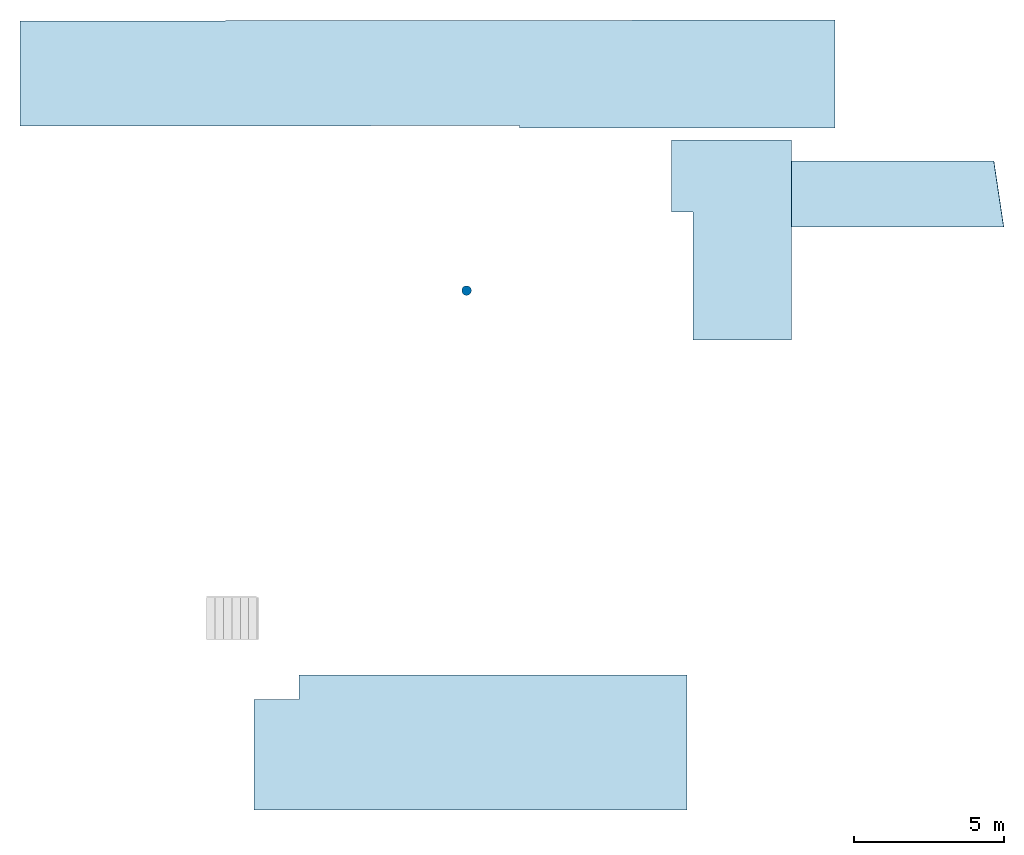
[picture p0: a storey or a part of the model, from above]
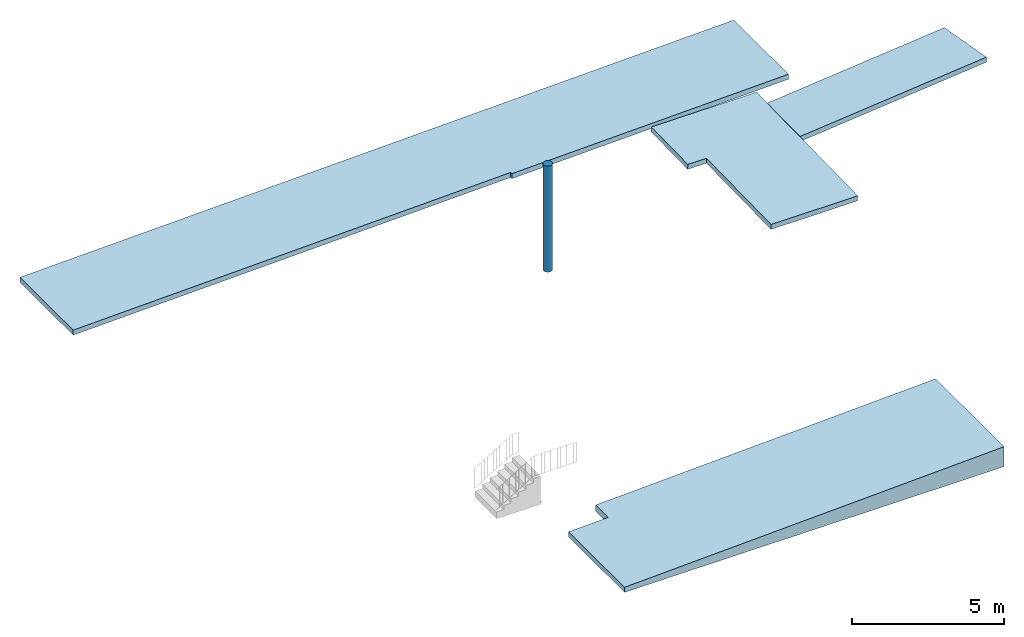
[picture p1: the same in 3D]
Properties of the parts of a building model (IFC2X3), part 1 of 3

# File
Description: ViewDefinition [CoordinationView_V2.0], RevitIdentifiers [VersionGUID: 12e980eb-f1c6-4dce-955d-64f03844660f, NumberOfSaves: 0], CoordinateReference [CoordinateBase: Coordonnées partagées]
File name: 0001
Time: 2023-09-28T10:16:39+01:00
Written by: ODA SDAI 22.12
Made in: 23.1.10.4 - Exporter 23.2.2.0 - Interface utilisateur alternative 23.2.2.0

# IfcProject, 0001
LongName: Nom du projet; Phase: Etat du projet

# IfcSite, Default
RefLatitude: 46, 9, 59, 999999; RefLongitude: 6, 8, 59, 999999; RefElevation: 0 m

# IfcSite: Site:Site, Site:Site:162049
Material: Peinture - Beige sable

# IfcBuilding
Pset_BuildingCommon - NumberOfStoreys: 6

# IfcBuildingStorey: Niveau:Pointe 8 mm (11)
Name | LongName | Elevation (m)
bloc-sanitaire | bloc-sanitaire | -7
GÉOMÈTRE estibal | GÉOMÈTRE estibal | -6
GÉOMÈTRE topo | GÉOMÈTRE topo | -5
GÉOMÈTRE avant bibliobus | GÉOMÈTRE avant bibliobus | -4
EDL RDC | EDL RDC | -3
EDL R+1 | EDL R+1 | -2
VS | VS | -1
REZ-DE-CHAUSSÉE | REZ-DE-CHAUSSÉE | 0
ÉTAGE | ÉTAGE | 3.06
TOITURE | TOITURE | 6.06
PLAN DE MASSE | PLAN DE MASSE | 9.06

# IfcBeam: Poutre-002 805777:Poutre-002 805777, Poutre-002
In: ÉTAGE
Type - Pset_BeamCommon - LoadBearing: yes; IsExternal: no
Material: Enduit - Beige nature
Pset_BeamCommon - Reference: BE béton 620 x 540
Pset_QuantityTakeOff - Reference: BE béton 620 x 540; sets with these values: 2

# IfcBeam: Poutre-002 805953:Poutre-002 805953, Poutre-002
In: ÉTAGE
Type - Pset_BeamCommon - LoadBearing: yes; IsExternal: no
Material: Peinture - Jade pâle
Pset_BeamCommon - Reference: BE acier 550 x 3000
Pset_QuantityTakeOff - Reference: BE acier 550 x 3000; sets with these values: 2

# IfcBeam: Poutre-004 250637:Poutre-004 250637 (5)
Type - Pset_BeamCommon - LoadBearing: yes; IsExternal: no
Material: Enduit - Beige nature
Pset_BeamCommon - Reference: BE béton 620 x 540
Pset_QuantityTakeOff - Reference: BE béton 620 x 540; sets with these values: 2
Name | In
Poutre-002 | TOITURE
Poutre-011 | ÉTAGE
Poutre-009 | ÉTAGE
Poutre-007 | ÉTAGE
Poutre-004 | ÉTAGE

# IfcBeam: Poutre-005 250586:Poutre-005 250586, Poutre-005
In: REZ-DE-CHAUSSÉE
Type - Pset_BeamCommon - LoadBearing: yes; IsExternal: no
Material: Enduit - Beige nature
Pset_BeamCommon - Reference: BE béton 620 x 540
Pset_QuantityTakeOff - Reference: BE béton 620 x 540; sets with these values: 2

# IfcBeam: Poutre-010 250417:Poutre-010 250417 (6)
Type - Pset_BeamCommon - LoadBearing: yes; IsExternal: no
Material: Peinture - Jade pâle
Pset_BeamCommon - Reference: BE acier 550 x 3000
Pset_QuantityTakeOff - Reference: BE acier 550 x 3000; sets with these values: 2
Name | In
Poutre-002 | TOITURE
Poutre-004 | ÉTAGE
Poutre-012 | ÉTAGE
Poutre-006 | ÉTAGE
Poutre-008 | ÉTAGE
Poutre-010 | ÉTAGE

# IfcBeam: Poutre-011 251190:Poutre-011 251190, Poutre-011
In: REZ-DE-CHAUSSÉE
Type - Pset_BeamCommon - LoadBearing: yes; IsExternal: no
Material: Enduit - Beige nature
Pset_BeamCommon - Reference: BE béton 620 x 540
Pset_QuantityTakeOff - Reference: BE béton 620 x 540; sets with these values: 2

# IfcBeam: Poutre-013 804316:Poutre-013 804316, Poutre-013
In: TOITURE
Type - Pset_BeamCommon - LoadBearing: yes; IsExternal: no
Material: Bois - Pin granuleux horizontal
Pset_BeamCommon - Reference: Bois - Massif 01 150 x 400
Pset_QuantityTakeOff - Reference: Bois - Massif 01 150 x 400; sets with these values: 2

# IfcBeam: Poutre-013 825176:Poutre-013 825176, Poutre-013
In: TOITURE
Type - Pset_BeamCommon - LoadBearing: yes; IsExternal: no
Material: Bois - Pin granuleux horizontal
Pset_BeamCommon - Reference: Bois - Massif 01 150 x 400
Pset_QuantityTakeOff - Reference: Bois - Massif 01 150 x 400; sets with these values: 2

# IfcBeam: Poutre-015 274921:Poutre-015 274921, Poutre-015
In: REZ-DE-CHAUSSÉE
Type - Pset_BeamCommon - LoadBearing: yes; IsExternal: no
Material: Bois - Pin granuleux horizontal
Pset_BeamCommon - Reference: Bois - Massif 01 200 x 150
Pset_QuantityTakeOff - Reference: Bois - Massif 01 200 x 150; sets with these values: 2

# IfcBeam: Poutre-017 441781:Poutre-017 441781, Poutre-017
In: ÉTAGE
Type - Pset_BeamCommon - LoadBearing: yes; IsExternal: no
Material: Peinture - Gris foncé
Pset_BeamCommon - Reference: grille 110x120 1100 x 1200
Pset_QuantityTakeOff - Reference: grille 110x120 1100 x 1200; sets with these values: 2

# IfcBeam: Poutre-017 448176:Poutre-017 448176 (5)
In: ÉTAGE
Type - Pset_BeamCommon - LoadBearing: yes; IsExternal: no
Material: Peinture - Gris foncé
Pset_BeamCommon - Reference: grille 110x170 1100 x 1700
Pset_QuantityTakeOff - Reference: grille 110x170 1100 x 1700; sets with these values: 2

# IfcBeam: Poutre-017 457192:Poutre-017 457192 (2)
In: ÉTAGE
Type - Pset_BeamCommon - LoadBearing: yes; IsExternal: no
Material: Peinture - Gris foncé
Pset_BeamCommon - Reference: grille 100x250 1000 x 2500
Pset_QuantityTakeOff - Reference: grille 100x250 1000 x 2500; sets with these values: 2

# IfcBeam: Poutre-017 458672:Poutre-017 458672 (4)
In: ÉTAGE
Type - Pset_BeamCommon - LoadBearing: yes; IsExternal: no
Material: Peinture - Gris foncé
Pset_BeamCommon - Reference: grille 50x245_1 510 x 2460
Pset_QuantityTakeOff - Reference: grille 50x245_1 510 x 2460; sets with these values: 2

# IfcBeam: Poutre-017 458855:Poutre-017 458855 (4)
In: ÉTAGE
Type - Pset_BeamCommon - LoadBearing: yes; IsExternal: no
Material: Peinture - Gris foncé
Pset_BeamCommon - Reference: grille 50x245_2 510 x 2460
Pset_QuantityTakeOff - Reference: grille 50x245_2 510 x 2460; sets with these values: 2

# IfcBeam: Poutre-017 459038:Poutre-017 459038 (4)
In: ÉTAGE
Type - Pset_BeamCommon - LoadBearing: yes; IsExternal: no
Material: Peinture - Gris foncé
Pset_BeamCommon - Reference: grille 50x245_3 510 x 2460
Pset_QuantityTakeOff - Reference: grille 50x245_3 510 x 2460; sets with these values: 2

# IfcBeam: Poutre-017 459230:Poutre-017 459230 (6)
In: ÉTAGE
Type - Pset_BeamCommon - LoadBearing: yes; IsExternal: no
Material: Peinture - Gris foncé
Pset_BeamCommon - Reference: grille 50x245_3 510 x 2460
Pset_QuantityTakeOff - Reference: grille 50x245_3 510 x 2460; sets with these values: 2

# IfcBeam: Poutre-017 459277:Poutre-017 459277 (6)
In: ÉTAGE
Type - Pset_BeamCommon - LoadBearing: yes; IsExternal: no
Material: Peinture - Gris foncé
Pset_BeamCommon - Reference: grille 50x245_2 510 x 2460
Pset_QuantityTakeOff - Reference: grille 50x245_2 510 x 2460; sets with these values: 2

# IfcBeam: Poutre-017 459324:Poutre-017 459324 (6)
In: ÉTAGE
Type - Pset_BeamCommon - LoadBearing: yes; IsExternal: no
Material: Peinture - Gris foncé
Pset_BeamCommon - Reference: grille 50x245_1 510 x 2460
Pset_QuantityTakeOff - Reference: grille 50x245_1 510 x 2460; sets with these values: 2

# IfcBeam: Poutre-018 48198:Poutre-018 48198 (2)
In: REZ-DE-CHAUSSÉE
Type - Pset_BeamCommon - LoadBearing: yes; IsExternal: no
Material: Peinture - Gris foncé
Pset_BeamCommon - Reference: grille 105x150 1050 x 1500
Pset_QuantityTakeOff - Reference: grille 105x150 1050 x 1500; sets with these values: 2

# IfcBeam: Poutre-019 150027:Poutre-019 150027, Poutre-019
In: ÉTAGE
Type - Pset_BeamCommon - LoadBearing: yes; IsExternal: no
Material: Peinture - Gris foncé
Pset_BeamCommon - Reference: Tube: C - simple 60 x 160
Pset_QuantityTakeOff - Reference: Tube: C - simple 60 x 160; sets with these values: 2

# IfcBeam: Poutre-019 150105:Poutre-019 150105 (2)
In: REZ-DE-CHAUSSÉE
Type - Pset_BeamCommon - LoadBearing: yes; IsExternal: no
Material: Peinture - Gris foncé
Pset_BeamCommon - Reference: IPN 200 70 x 140
Pset_QuantityTakeOff - Reference: IPN 200 70 x 140; sets with these values: 2

# IfcBeam: Poutre-019 150203:Poutre-019 150203 (5)
In: REZ-DE-CHAUSSÉE
Type - Pset_BeamCommon - LoadBearing: yes; IsExternal: no
Material: Peinture - Gris foncé
Pset_BeamCommon - Reference: IPN 200 70 x 140
Pset_QuantityTakeOff - Reference: IPN 200 70 x 140; sets with these values: 2

# IfcBeam: Poutre-019 150363:Poutre-019 150363, Poutre-019
In: ÉTAGE
Type - Pset_BeamCommon - LoadBearing: yes; IsExternal: no
Material: Peinture - Gris foncé
Pset_BeamCommon - Reference: Tube: C - simple 60 x 140
Pset_QuantityTakeOff - Reference: Tube: C - simple 60 x 140; sets with these values: 2

# IfcBeam: Poutre-019 150414:Poutre-019 150414, Poutre-019
In: ÉTAGE
Type - Pset_BeamCommon - LoadBearing: yes; IsExternal: no
Material: Peinture - Gris foncé
Pset_BeamCommon - Reference: Tube: C - simple 60 x 140
Pset_QuantityTakeOff - Reference: Tube: C - simple 60 x 140; sets with these values: 2

# IfcBeam: Poutre-019 150508:Poutre-019 150508, Poutre-019
In: ÉTAGE
Type - Pset_BeamCommon - LoadBearing: yes; IsExternal: no
Material: Métal - Acier
Pset_BeamCommon - Reference: IPN 200 50 x 100
Pset_QuantityTakeOff - Reference: IPN 200 50 x 100; sets with these values: 2

# IfcBeam: Poutre-019 150673:Poutre-019 150673, Poutre-019
In: ÉTAGE
Type - Pset_BeamCommon - LoadBearing: yes; IsExternal: no
Material: Métal - Acier
Pset_BeamCommon - Reference: IPN 200 50 x 100
Pset_QuantityTakeOff - Reference: IPN 200 50 x 100; sets with these values: 2

# IfcBeam: Poutre-019 150740:Poutre-019 150740, Poutre-019
In: ÉTAGE
Type - Pset_BeamCommon - LoadBearing: yes; IsExternal: no
Material: Métal - Acier
Pset_BeamCommon - Reference: IPN 200 50 x 100
Pset_QuantityTakeOff - Reference: IPN 200 50 x 100; sets with these values: 2

# IfcBeam: Poutre-019 150807:Poutre-019 150807, Poutre-019
In: ÉTAGE
Type - Pset_BeamCommon - LoadBearing: yes; IsExternal: no
Material: Métal - Acier
Pset_BeamCommon - Reference: IPN 200 50 x 100
Pset_QuantityTakeOff - Reference: IPN 200 50 x 100; sets with these values: 2

# IfcBeam: Poutre-019 150874:Poutre-019 150874, Poutre-019
In: ÉTAGE
Type - Pset_BeamCommon - LoadBearing: yes; IsExternal: no
Material: Métal - Acier
Pset_BeamCommon - Reference: IPN 200 50 x 100
Pset_QuantityTakeOff - Reference: IPN 200 50 x 100; sets with these values: 2

# IfcBeam: Poutre-019 19330:Poutre-019 19330, Poutre-019
In: ÉTAGE
Type - Pset_BeamCommon - LoadBearing: yes; IsExternal: no
Material: Peinture - Gris foncé
Pset_BeamCommon - Reference: Tube: C - simple 70 x 180
Pset_QuantityTakeOff - Reference: Tube: C - simple 70 x 180; sets with these values: 2

# IfcBeam: Poutre-019 56232:Poutre-019 56232, Poutre-019
In: ÉTAGE
Type - Pset_BeamCommon - LoadBearing: yes; IsExternal: no
Material: Peinture - Gris foncé
Pset_BeamCommon - Reference: Tube: C - simple 70 x 100
Pset_QuantityTakeOff - Reference: Tube: C - simple 70 x 100; sets with these values: 2

# IfcBuildingElementProxy: Poutre-001 244787:Poutre-001 244787, Poutre-001 244787:Poutre-001 244787:151923
In: ÉTAGE
Type - Material: Bois - Chêne clair
Pset_BuildingElementProxyCommon - Reference: Poutre-001 244787; sets with these values: 2

# IfcBuildingElementProxy: Poutre-001 248392:Poutre-001 248392, Poutre-001 248392:Poutre-001 248392:151969
In: ÉTAGE
Type - Material: Bois - Chêne clair
Pset_BuildingElementProxyCommon - Reference: Poutre-001 248392; sets with these values: 2

# IfcBuildingElementProxy: Poutre-001:Poutre-001, Poutre-001:Poutre-001:147980
In: REZ-DE-CHAUSSÉE
Type - Material: Bois - Chêne clair
Pset_BuildingElementProxyCommon - Reference: Poutre-001; sets with these values: 2

# IfcBuildingElementProxy: Poutre-016 844062:Poutre-016 844062, Poutre-016 844062:Poutre-016 844062:161965
In: REZ-DE-CHAUSSÉE
Type - Material: Peinture - Gris foncé
Pset_BuildingElementProxyCommon - Reference: Poutre-016 844062; sets with these values: 2
Pset_ProvisionForVoid - Width: 0.06 m; Height: 0.04 m; Depth: 0.04 m

# IfcBuildingElementProxy: Poutre-016:Poutre-016, Poutre-016:Poutre-016:161553
In: TOITURE
Type - Material: Peinture - Gris foncé
Pset_BuildingElementProxyCommon - Reference: Poutre-016; sets with these values: 2

# IfcBuildingElementProxy: Symb-0001 (6)
Type - Material: Déco - Céramique / Porcelaine
Pset_BuildingElementProxyCommon - sets with these values: 2
Name | In | Reference
Symb-0001:Symb-0001:148294 | REZ-DE-CHAUSSÉE | Symb-0001
Symb-0001 105909:Symb-0001 105909:150008 | REZ-DE-CHAUSSÉE | Symb-0001 105909
Symb-0001 265598:Symb-0001 265598:152434 | ÉTAGE | Symb-0001 265598
Symb-0001 267370:Symb-0001 267370:152441 | ÉTAGE | Symb-0001 267370
Symb-0001 271945:Symb-0001 271945:152448 | ÉTAGE | Symb-0001 271945
Symb-0001 801620:Symb-0001 801620:161433 | ÉTAGE | Symb-0001 801620

# IfcBuildingElementProxy: Symb-0001, Symb-0001 47900:Symb-0001 47900:148666
In: REZ-DE-CHAUSSÉE
Type - Material: Marbre - Blanc beige
Pset_BuildingElementProxyCommon - Reference: Symb-0001 47900; sets with these values: 2

# IfcBuildingElementProxy: Symb-0001, Symb-0001 249329:Symb-0001 249329:152008
In: ÉTAGE
Type - Material: Peinture - Gris foncé
Pset_BuildingElementProxyCommon - Reference: Symb-0001 249329; sets with these values: 2

# IfcBuildingElementProxy: Symb-0002 (2)
In: ÉTAGE
Type - Material: Métal - Chrome, Métal - Zinc, Peinture - Blanc titanium, Peinture - Noir, Transp. - Verre bleuté, Métal - Fer 16274
Pset_BuildingElementProxyCommon - sets with these values: 2
Name | Reference
Symb-0002 440074:Symb-0002 440074:156005 | Symb-0002 440074
Symb-0002 453781:Symb-0002 453781:158489 | Symb-0002 453781

# IfcBuildingElementProxy: Symb-0002 (3)
In: TOITURE
Type - Material: Métal - Zinc
Pset_BuildingElementProxyCommon - sets with these values: 2
Pset_ProvisionForVoid - Width: 0.3 m; Height: 0.3 m; Depth: 0.3 m
Name | Reference
Symb-0002 824208:Symb-0002 824208:161709 | Symb-0002 824208
Symb-0002 842974:Symb-0002 842974:161895 | Symb-0002 842974
Symb-0002 843032:Symb-0002 843032:161916 | Symb-0002 843032

# IfcBuildingElementProxy: Symb-0002, Symb-0002:Symb-0002:151962
In: ÉTAGE
Type - Material: Peinture - Anthracite
Pset_BuildingElementProxyCommon - Reference: Symb-0002; sets with these values: 2

# IfcBuildingElementProxy: Symb-0003 (17)
Type - Material: Bois - Chêne clair
Pset_BuildingElementProxyCommon - sets with these values: 2
Name | In | Reference | Width (m) | Height (m) = Depth (m)
Symb-0003:Symb-0003:148089 | REZ-DE-CHAUSSÉE | Symb-0003 | 0.1 | 0.02
Symb-0003 60907:Symb-0003 60907:148702 | REZ-DE-CHAUSSÉE | Symb-0003 60907 | 0.1 | 0.02
Symb-0003 60936:Symb-0003 60936:148765 | REZ-DE-CHAUSSÉE | Symb-0003 60936 | 0.1 | 0.02
Symb-0003 60965:Symb-0003 60965:148828 | REZ-DE-CHAUSSÉE | Symb-0003 60965 | 0.1 | 0.02
Symb-0003 60994:Symb-0003 60994:148891 | REZ-DE-CHAUSSÉE | Symb-0003 60994 | 0.1 | 0.02
Symb-0003 61023:Symb-0003 61023:148954 | REZ-DE-CHAUSSÉE | Symb-0003 61023 | 0.1 | 0.02
Symb-0003 62364:Symb-0003 62364:149017 | REZ-DE-CHAUSSÉE | Symb-0003 62364 | 0.102 | 0.02
Symb-0003 62445:Symb-0003 62445:149199 | REZ-DE-CHAUSSÉE | Symb-0003 62445 | 0.102 | 0.02
Symb-0003 63828:Symb-0003 63828:149381 | REZ-DE-CHAUSSÉE | Symb-0003 63828 | 0.102 | 0.02
Symb-0003 65325:Symb-0003 65325:149563 | REZ-DE-CHAUSSÉE | Symb-0003 65325 | 0.1 | 0.02
Symb-0003 104089:Symb-0003 104089:149819 | REZ-DE-CHAUSSÉE | Symb-0003 104089 | 0.1 | 0.02
Symb-0003 133649:Symb-0003 133649:150591 | REZ-DE-CHAUSSÉE | Symb-0003 133649 | 0.1 | 0.02
Symb-0003 134108:Symb-0003 134108:150661 | REZ-DE-CHAUSSÉE | Symb-0003 134108 | 0.1 | 0.02
Symb-0003 134189:Symb-0003 134189:150724 | REZ-DE-CHAUSSÉE | Symb-0003 134189 | 0.1 | 0.02
Symb-0003 134270:Symb-0003 134270:150787 | REZ-DE-CHAUSSÉE | Symb-0003 134270 | 0.1 | 0.02
Symb-0003 134351:Symb-0003 134351:150850 | REZ-DE-CHAUSSÉE | Symb-0003 134351 | 0.1 | 0.02
Symb-0003 290547:Symb-0003 290547:155177 | ÉTAGE | Symb-0003 290547 | 3.44 | 0.05

# IfcBuildingElementProxy: Symb-0003 (3)
In: ÉTAGE
Type - Material: Métal - Zinc
Pset_BuildingElementProxyCommon - sets with these values: 2
Name | Reference
Symb-0003 824296:Symb-0003 824296:161723 | Symb-0003 824296
Symb-0003 842945:Symb-0003 842945:161888 | Symb-0003 842945
Symb-0003 843003:Symb-0003 843003:161909 | Symb-0003 843003

# IfcBuildingElementProxy: Symb-0003 (11)
Type - Material: Peinture - Anthracite
Pset_BuildingElementProxyCommon - sets with these values: 2
Name | In | Reference | Width (m) | Height (m) = Depth (m)
Symb-0003 46987:Symb-0003 46987:148501 | REZ-DE-CHAUSSÉE | Symb-0003 46987 | 2.2 | 3.3
Symb-0003 254697:Symb-0003 254697:152288 | ÉTAGE | Symb-0003 254697 | 2.48 | 3.4
Symb-0003 274880:Symb-0003 274880:152455 | ÉTAGE | Symb-0003 274880
Symb-0003 282040:Symb-0003 282040:152468 | ÉTAGE | Symb-0003 282040 | 2.76 | 3.3
Symb-0003 285634:Symb-0003 285634:153152 | ÉTAGE | Symb-0003 285634 | 2.15 | 3
Symb-0003 297244:Symb-0003 297244:155510 | ÉTAGE | Symb-0003 297244 | 0.04 | 0.01
Symb-0003 299875:Symb-0003 299875:155608 | ÉTAGE | Symb-0003 299875 | 5.25 | 0.04
Symb-0003 463800:Symb-0003 463800:158503 | REZ-DE-CHAUSSÉE | Symb-0003 463800
Symb-0003 467921:Symb-0003 467921:160031 | ÉTAGE | Symb-0003 467921 | 3.4 | 0.04
Symb-0003 470760:Symb-0003 470760:160276 | ÉTAGE | Symb-0003 470760 | 5.55 | 0.04
Symb-0003 472838:Symb-0003 472838:160661 | ÉTAGE | Symb-0003 472838 | 2.48 | 3.3

# IfcBuildingElementProxy: Symb-0003 (18)
In: ÉTAGE
Type - Material: Peinture - Gris foncé
Pset_BuildingElementProxyCommon - sets with these values: 2
Pset_ProvisionForVoid - Width: 0.04 m; Height: 0.04 m; Depth: 0.04 m
Name | Reference
Symb-0003 283937:Symb-0003 283937:152675 | Symb-0003 283937
Symb-0003 284028:Symb-0003 284028:152905 | Symb-0003 284028
Symb-0003 285663:Symb-0003 285663:153317 | Symb-0003 285663
Symb-0003 285692:Symb-0003 285692:153547 | Symb-0003 285692
Symb-0003 285721:Symb-0003 285721:153777 | Symb-0003 285721
Symb-0003 287706:Symb-0003 287706:154230 | Symb-0003 287706
Symb-0003 288161:Symb-0003 288161:154474 | Symb-0003 288161
Symb-0003 288190:Symb-0003 288190:154704 | Symb-0003 288190
Symb-0003 288219:Symb-0003 288219:154934 | Symb-0003 288219
Symb-0003 464579:Symb-0003 464579:158979 | Symb-0003 464579
Symb-0003 464608:Symb-0003 464608:159079 | Symb-0003 464608
Symb-0003 464637:Symb-0003 464637:159179 | Symb-0003 464637
Symb-0003 464666:Symb-0003 464666:159279 | Symb-0003 464666
Symb-0003 464695:Symb-0003 464695:159379 | Symb-0003 464695
Symb-0003 464724:Symb-0003 464724:159479 | Symb-0003 464724
Symb-0003 464753:Symb-0003 464753:159579 | Symb-0003 464753
Symb-0003 464782:Symb-0003 464782:159679 | Symb-0003 464782
Symb-0003 464811:Symb-0003 464811:159779 | Symb-0003 464811

# IfcBuildingElementProxy: Symb-0004 (10)
In: REZ-DE-CHAUSSÉE
Type - Material: Air - Vide d'air
Pset_BuildingElementProxyCommon - sets with these values: 2
Name | Reference
Symb-0004:Symb-0004:148694 | Symb-0004
Symb-0004 86494:Symb-0004 86494:149763 | Symb-0004 86494
Symb-0004 87821:Symb-0004 87821:149770 | Symb-0004 87821
Symb-0004 89785:Symb-0004 89785:149777 | Symb-0004 89785
Symb-0004 92138:Symb-0004 92138:149784 | Symb-0004 92138
Symb-0004 93556:Symb-0004 93556:149791 | Symb-0004 93556
Symb-0004 96958:Symb-0004 96958:149798 | Symb-0004 96958
Symb-0004 100234:Symb-0004 100234:149805 | Symb-0004 100234
Symb-0004 103848:Symb-0004 103848:149812 | Symb-0004 103848
Symb-0004 129922:Symb-0004 129922:150575 | Symb-0004 129922

# IfcBuildingElementProxy: Symb-0004, Symb-0004 124967:Symb-0004 124967:150022
In: VS
Type - Material: Peinture - Gris clair
Pset_BuildingElementProxyCommon - Reference: Symb-0004 124967; sets with these values: 2

# IfcBuildingElementProxy: Symb-0004 (2)
In: ÉTAGE
Type - Material: Peinture - Gris foncé
Pset_BuildingElementProxyCommon - sets with these values: 2
Pset_ProvisionForVoid - Width: 0.02 m; Height: 0.04 m; Depth: 0.04 m
Name | Reference
Symb-0004 286920:Symb-0004 286920:154123 | Symb-0004 286920
Symb-0004 466004:Symb-0004 466004:159879 | Symb-0004 466004

# IfcColumn: Pot-001 17298:Pot-001 17298, Pot-001
In: EDL R+1
Type - PredefinedType: COLUMN; Material: <Unnamed>, Surface-Blanc
Type - Pset_ColumnCommon - LoadBearing: yes; IsExternal: no
Material: Surface-Blanc
Pset_ColumnCommon - Reference: Struct. - Pierre D320
Pset_QuantityTakeOff - Reference: Struct. - Pierre D320; sets with these values: 2

# IfcColumn: Pot-001 17357:Pot-001 17357 (6)
In: REZ-DE-CHAUSSÉE
Type - PredefinedType: COLUMN; Material: Surface-Blanc
Type - Pset_ColumnCommon - LoadBearing: yes; IsExternal: no
Pset_ColumnCommon - Reference: Struct. - Pierre D340
Pset_QuantityTakeOff - Reference: Struct. - Pierre D340; sets with these values: 2
Name
2 x Pot-003
2 x Pot-002
2 x Pot-001

# IfcColumn: Pot-003 25818:Pot-003 25818 (2)
In: REZ-DE-CHAUSSÉE
Type - PredefinedType: COLUMN; Material: Enduit - Beige nature
Type - Pset_ColumnCommon - LoadBearing: yes; IsExternal: no
Pset_ColumnCommon - Reference: Struct. - Pierre 260 x 260
Pset_QuantityTakeOff - Reference: Struct. - Pierre 260 x 260; sets with these values: 2
Name
Pot-004
Pot-003

# IfcColumn: Pot-005 285852:Pot-005 285852, Pot-005 285852:Pot-005 285852:154036
In: ÉTAGE
Type - PredefinedType: COLUMN; Material: Peinture - Gris foncé
Type - Pset_ColumnCommon - IsExternal: no
Pset_ColumnCommon - Reference: Pot-005 285852
Pset_QuantityTakeOff - Reference: Pot-005 285852; sets with these values: 2

# IfcColumn: Pot-005 285958:Pot-005 285958, Pot-005 285958:Pot-005 285958:154065
In: ÉTAGE
Type - PredefinedType: COLUMN; Material: Peinture - Gris foncé
Type - Pset_ColumnCommon - IsExternal: no
Pset_ColumnCommon - Reference: Pot-005 285958
Pset_QuantityTakeOff - Reference: Pot-005 285958; sets with these values: 2

# IfcColumn: Pot-005 286064:Pot-005 286064, Pot-005 286064:Pot-005 286064:154094
In: ÉTAGE
Type - PredefinedType: COLUMN; Material: Peinture - Gris foncé
Type - Pset_ColumnCommon - IsExternal: no
Pset_ColumnCommon - Reference: Pot-005 286064
Pset_QuantityTakeOff - Reference: Pot-005 286064; sets with these values: 2

# IfcColumn: Pot-005 441838:Pot-005 441838 (65)
In: ÉTAGE
Type - PredefinedType: COLUMN; Material: Peinture - Gris foncé
Type - Pset_ColumnCommon - LoadBearing: yes; IsExternal: no
Pset_ColumnCommon - Reference: Métal - Fer 6 x 30
Pset_QuantityTakeOff - Reference: Métal - Fer 6 x 30; sets with these values: 2

# IfcColumn: Pot-005 447493:Pot-005 447493 (32)
In: ÉTAGE
Type - PredefinedType: COLUMN; Material: Peinture - Gris foncé
Type - Pset_ColumnCommon - LoadBearing: yes; IsExternal: no
Pset_ColumnCommon - Reference: Métal - Fer 30 x 6
Pset_QuantityTakeOff - Reference: Métal - Fer 30 x 6; sets with these values: 2

# IfcColumn: Pot-005 459659:Pot-005 459659, Pot-005
In: ÉTAGE
Type - PredefinedType: COLUMN; Material: <Unnamed>, Peinture - Gris foncé
Type - Pset_ColumnCommon - LoadBearing: yes; IsExternal: no
Material: Peinture - Gris foncé
Pset_ColumnCommon - Reference: Métal - Fer 80 x 140
Pset_QuantityTakeOff - Reference: Métal - Fer 80 x 140; sets with these values: 2

# IfcColumn: Pot-005:Pot-005, Pot-005:Pot-005:154007
In: ÉTAGE
Type - PredefinedType: COLUMN; Material: Peinture - Gris foncé
Type - Pset_ColumnCommon - IsExternal: no
Pset_ColumnCommon - Reference: Pot-005
Pset_QuantityTakeOff - Reference: Pot-005; sets with these values: 2

# IfcColumn: Pot-006 103892:Pot-006 103892 (24)
In: REZ-DE-CHAUSSÉE
Type - PredefinedType: COLUMN; Material: Peinture - Gris foncé
Type - Pset_ColumnCommon - LoadBearing: yes; IsExternal: no
Pset_ColumnCommon - Reference: Métal - Fer 100 x 50
Pset_QuantityTakeOff - Reference: Métal - Fer 100 x 50; sets with these values: 2
Name
20 x Pot-007
4 x Pot-006

# IfcColumn: Pot-006 134395:Pot-006 134395, Pot-006
In: VS
Type - PredefinedType: COLUMN; Material: <Unnamed>, Peinture - Gris foncé
Type - Pset_ColumnCommon - LoadBearing: yes; IsExternal: no
Material: Peinture - Gris foncé
Pset_ColumnCommon - Reference: Métal - Fer 10 x 100
Pset_QuantityTakeOff - Reference: Métal - Fer 10 x 100; sets with these values: 2

# IfcColumn: Pot-006 56846:Pot-006 56846 (23)
In: REZ-DE-CHAUSSÉE
Type - PredefinedType: COLUMN; Material: Peinture - Gris foncé
Type - Pset_ColumnCommon - LoadBearing: yes; IsExternal: no
Pset_ColumnCommon - Reference: Métal - Fer 50 x 100
Pset_QuantityTakeOff - Reference: Métal - Fer 50 x 100; sets with these values: 2

# IfcColumn: Pot-008 40407:Pot-008 40407 (4)
In: REZ-DE-CHAUSSÉE
Type - PredefinedType: COLUMN; Material: Bois - Chêne clair
Type - Pset_ColumnCommon - LoadBearing: yes; IsExternal: no
Pset_ColumnCommon - Reference: Bois - Massif 01 70 x 140
Pset_QuantityTakeOff - Reference: Bois - Massif 01 70 x 140; sets with these values: 2
Name
Pot-007
3 x Pot-008

# IfcColumn: Pot-010 24125:Pot-010 24125, Pot-010
In: REZ-DE-CHAUSSÉE
Type - PredefinedType: COLUMN; Material: <Unnamed>, Bois - Chêne clair
Type - Pset_ColumnCommon - LoadBearing: yes; IsExternal: no
Material: Bois - Chêne clair
Pset_ColumnCommon - Reference: Bois - Massif 01 60 x 140
Pset_QuantityTakeOff - Reference: Bois - Massif 01 60 x 140; sets with these values: 2

# IfcColumn: Pot-011 135416:Pot-011 135416 (3)
In: REZ-DE-CHAUSSÉE
Type - PredefinedType: COLUMN; Material: Béton - Lissé
Type - Pset_ColumnCommon - LoadBearing: yes; IsExternal: no
Pset_ColumnCommon - Reference: Struct. - Béton 100 x 100
Pset_QuantityTakeOff - Reference: Struct. - Béton 100 x 100; sets with these values: 2

# IfcColumn: Pot-011 135587:Pot-011 135587, Pot-011
In: VS
Type - PredefinedType: COLUMN; Material: <Unnamed>, Béton - Lissé
Type - Pset_ColumnCommon - LoadBearing: yes; IsExternal: no
Material: Béton - Lissé
Pset_ColumnCommon - Reference: Struct. - Béton 100 x 100
Pset_QuantityTakeOff - Reference: Struct. - Béton 100 x 100; sets with these values: 2

# IfcColumn: Pot-012 448235:Pot-012 448235 (2)
In: ÉTAGE
Type - PredefinedType: COLUMN; Material: Peinture - Gris foncé
Type - Pset_ColumnCommon - LoadBearing: yes; IsExternal: no
Pset_ColumnCommon - Reference: Bois - Massif 01 240 x 120
Pset_QuantityTakeOff - Reference: Bois - Massif 01 240 x 120; sets with these values: 2

# IfcDiscreteAccessory: Symb-0003 (17)
In: REZ-DE-CHAUSSÉE
Type - Material: Bois - Chêne clair
Name | Reference
Symb-0003 449563:Symb-0003 449563:156160 | Symb-0003 449563
Symb-0003 449597:Symb-0003 449597:156297 | Symb-0003 449597
Symb-0003 449627:Symb-0003 449627:156434 | Symb-0003 449627
Symb-0003 449657:Symb-0003 449657:156571 | Symb-0003 449657
Symb-0003 449687:Symb-0003 449687:156708 | Symb-0003 449687
Symb-0003 450779:Symb-0003 450779:156845 | Symb-0003 450779
Symb-0003 451881:Symb-0003 451881:156982 | Symb-0003 451881
Symb-0003 451911:Symb-0003 451911:157119 | Symb-0003 451911
Symb-0003 451941:Symb-0003 451941:157256 | Symb-0003 451941
Symb-0003 453043:Symb-0003 453043:157393 | Symb-0003 453043
Symb-0003 453073:Symb-0003 453073:157530 | Symb-0003 453073
Symb-0003 453103:Symb-0003 453103:157667 | Symb-0003 453103
Symb-0003 453133:Symb-0003 453133:157804 | Symb-0003 453133
Symb-0003 453163:Symb-0003 453163:157941 | Symb-0003 453163
Symb-0003 453193:Symb-0003 453193:158078 | Symb-0003 453193
Symb-0003 453223:Symb-0003 453223:158215 | Symb-0003 453223
Symb-0003 453253:Symb-0003 453253:158352 | Symb-0003 453253

# IfcDiscreteAccessory: Symb-0004, Symb-0004 240046:Symb-0004 240046:151657
In: ÉTAGE
Type - Material: Peinture - Blanc titanium
Pset_QuantityTakeOff - Reference: Symb-0004 240046

# IfcDiscreteAccessory: Symb-0005, Symb-0005:Symb-0005:151706
In: REZ-DE-CHAUSSÉE
Type - Material: Peinture - Blanc titanium
Pset_QuantityTakeOff - Reference: Symb-0005

# IfcDiscreteAccessory: Symb-0006, Symb-0006 240113:Symb-0006 240113:151752
In: ÉTAGE
Type - Material: Peinture - Blanc titanium
Pset_QuantityTakeOff - Reference: Symb-0006 240113

# IfcDiscreteAccessory: Symb-0007, Symb-0007 240143:Symb-0007 240143:151798
In: REZ-DE-CHAUSSÉE
Type - Material: Peinture - Blanc titanium
Pset_QuantityTakeOff - Reference: Symb-0007 240143

# IfcDiscreteAccessory: Symb-0008, Symb-0008 240173:Symb-0008 240173:151844
In: REZ-DE-CHAUSSÉE
Type - Material: Peinture - Blanc titanium
Pset_QuantityTakeOff - Reference: Symb-0008 240173

# IfcDistributionElement: Symb-0001, Symb-0001 149866:Symb-0001 149866:151087
In: VS
Type - Material: Peinture - Blanc brillant
Pset_QuantityTakeOff - Reference: Symb-0001 149866

# IfcDoor: Por-002, Por-002 139030:Por-002 139030:196505
In: REZ-DE-CHAUSSÉE
Type - OperationType: DOUBLE_DOOR_SINGLE_SWING; ParameterTakesPrecedence: no; Sizeable: no; Material: Peinture - Anthracite
Type - Por-002 139030:Por-002 139030:196505:1 - PanelOperation: SWINGING
Type - Pset_DoorCommon - IsExternal: no
OverallHeight: 2.42 m; OverallWidth: 1.29 m
Pset_DoorCommon - IsExternal: yes; Reference: Por-002 139030
Pset_QuantityTakeOff - Reference: Por-002 139030

# IfcDoor: Por-002, Por-002 17063:Por-002 17063:195863
In: REZ-DE-CHAUSSÉE
Type - OperationType: ROLLINGUP; ParameterTakesPrecedence: no; Sizeable: no; Material: Peinture - Anthracite
Type - Por-002 17063:Por-002 17063:195863:1 - PanelOperation: ROLLINGUP
Type - Pset_DoorCommon - IsExternal: no; ThermalTransmittance: 0 kg/K/s3
OverallHeight: 3.5 m; OverallWidth: 4 m
Pset_DoorCommon - IsExternal: yes; Reference: Por-002 17063
Pset_QuantityTakeOff - Reference: Por-002 17063

# IfcDoor: Por-002, Por-002 137667:Por-002 137667:196503
In: REZ-DE-CHAUSSÉE
Type - OperationType: SINGLE_SWING_LEFT; ParameterTakesPrecedence: no; Sizeable: no; Material: Peinture - Anthracite
Type - Por-002 137667:Por-002 137667:196503:1 - PanelOperation: SWINGING
Type - Pset_DoorCommon - IsExternal: no
OverallHeight: 2.17 m; OverallWidth: 1.03 m
Pset_DoorCommon - IsExternal: yes; Reference: Por-002 137667
Pset_QuantityTakeOff - Reference: Por-002 137667

# IfcDoor: Por-003, Por-003 12459:Por-003 12459:195840
In: REZ-DE-CHAUSSÉE
Type - OperationType: DOUBLE_DOOR_SINGLE_SWING; ParameterTakesPrecedence: no; Sizeable: no; Material: Peinture - Gris clair
Type - Por-003 12459:Por-003 12459:195840:1 - PanelOperation: SWINGING
Type - Pset_DoorCommon - IsExternal: no
OverallHeight: 2.09 m; OverallWidth: 1.67 m
Pset_DoorCommon - IsExternal: yes; Reference: Por-003 12459
Pset_QuantityTakeOff - Reference: Por-003 12459

# IfcDoor: Por-003, Por-003 18623:Por-003 18623:195873
In: REZ-DE-CHAUSSÉE
Type - OperationType: DOUBLE_DOOR_SINGLE_SWING; ParameterTakesPrecedence: no; Sizeable: no; Material: Peinture - Gris clair
Type - Por-003 18623:Por-003 18623:195873:1 - PanelOperation: SWINGING
Type - Pset_DoorCommon - IsExternal: no
OverallHeight: 2.09 m; OverallWidth: 1.33 m
Pset_DoorCommon - IsExternal: yes; Reference: Por-003 18623
Pset_QuantityTakeOff - Reference: Por-003 18623

# IfcDoor: Por-003, Por-003 22154:Por-003 22154:195907
In: REZ-DE-CHAUSSÉE
Type - OperationType: DOUBLE_DOOR_SINGLE_SWING; ParameterTakesPrecedence: no; Sizeable: no; Material: Peinture - Gris clair
Type - Por-003 22154:Por-003 22154:195907:1 - PanelOperation: SWINGING
Type - Pset_DoorCommon - IsExternal: no
OverallHeight: 2.09 m; OverallWidth: 1.44 m
Pset_DoorCommon - IsExternal: yes; Reference: Por-003 22154
Pset_QuantityTakeOff - Reference: Por-003 22154

# IfcDoor: Por-003, Por-003 24077:Por-003 24077:195930
In: REZ-DE-CHAUSSÉE
Type - OperationType: DOUBLE_DOOR_SINGLE_SWING; ParameterTakesPrecedence: no; Sizeable: no; Material: Peinture - Gris clair
Type - Por-003 24077:Por-003 24077:195930:1 - PanelOperation: SWINGING
Type - Pset_DoorCommon - IsExternal: no
OverallHeight: 2.09 m; OverallWidth: 1.95 m
Pset_DoorCommon - IsExternal: yes; Reference: Por-003 24077
Pset_QuantityTakeOff - Reference: Por-003 24077

# IfcDoor: Por-003, Por-003 147138:Por-003 147138:196539
In: REZ-DE-CHAUSSÉE
Type - OperationType: SINGLE_SWING_LEFT; ParameterTakesPrecedence: no; Sizeable: no; Material: Métal - Acier inoxydable
Type - Por-003 147138:Por-003 147138:196539:1 - PanelOperation: SWINGING
Type - Pset_DoorCommon - IsExternal: no
OverallHeight: 2.05 m; OverallWidth: 1 m
Pset_DoorCommon - IsExternal: yes; Reference: Por-003 147138
Pset_QuantityTakeOff - Reference: Por-003 147138

# IfcDoor: Por-003 (2)
Type - OperationType: SINGLE_SWING_LEFT; ParameterTakesPrecedence: no; Sizeable: no; Material: Peinture - Gris clair
Type - Por-003 11722:Por-003 11722:195834:1 - PanelOperation: SWINGING
Type - Pset_DoorCommon - IsExternal: no
OverallHeight: 2.09 m; OverallWidth: 1 m
Pset_DoorCommon - Reference: Por-003 11722
Pset_QuantityTakeOff - Reference: Por-003 11722
Name (Por-003 11722:Por-003 11722:...) | In
195834 | REZ-DE-CHAUSSÉE | Pset_DoorCommon - IsExternal: yes
197922 | ÉTAGE

# IfcDoor: Por-003, Por-003 11722:Por-003 11722:197919
In: ÉTAGE
Type - OperationType: SINGLE_SWING_LEFT; ParameterTakesPrecedence: no; Sizeable: no; Material: Peinture - Gris clair
Type - Por-003 11722:Por-003 11722:197919:1 - PanelOperation: SWINGING
Type - Pset_DoorCommon - IsExternal: no
OverallHeight: 2.09 m; OverallWidth: 1 m
Pset_DoorCommon - Reference: Por-003 11722
Pset_QuantityTakeOff - Reference: Por-003 11722

# IfcDoor: Por-003, Por-003 22620:Por-003 22620:195923
In: REZ-DE-CHAUSSÉE
Type - OperationType: SINGLE_SWING_LEFT; ParameterTakesPrecedence: no; Sizeable: no; Material: Peinture - Gris clair
Type - Por-003 22620:Por-003 22620:195923:1 - PanelOperation: SWINGING
Type - Pset_DoorCommon - IsExternal: no
OverallHeight: 2.09 m; OverallWidth: 1.03 m
Pset_DoorCommon - IsExternal: yes; Reference: Por-003 22620
Pset_QuantityTakeOff - Reference: Por-003 22620

# IfcDoor: Por-003, Por-003 22620:Por-003 22620:195928
In: REZ-DE-CHAUSSÉE
Type - OperationType: SINGLE_SWING_LEFT; ParameterTakesPrecedence: no; Sizeable: no; Material: Peinture - Gris clair
Type - Por-003 22620:Por-003 22620:195928:1 - PanelOperation: SWINGING
Type - Pset_DoorCommon - IsExternal: no
OverallHeight: 2.09 m; OverallWidth: 1.03 m
Pset_DoorCommon - Reference: Por-003 22620
Pset_QuantityTakeOff - Reference: Por-003 22620

# IfcDoor: Por-003, Por-003 257436:Por-003 257436:198215
In: ÉTAGE
Type - OperationType: SINGLE_SWING_LEFT; ParameterTakesPrecedence: no; Sizeable: no; Material: Peinture - Gris clair
Type - Por-003 257436:Por-003 257436:198215:1 - PanelOperation: SWINGING
Type - Pset_DoorCommon - IsExternal: no
OverallHeight: 2.09 m; OverallWidth: 1.03 m
Pset_DoorCommon - IsExternal: yes; Reference: Por-003 257436
Pset_QuantityTakeOff - Reference: Por-003 257436

# IfcDoor: Por-003, Por-003 9927:Por-003 9927:195816
In: REZ-DE-CHAUSSÉE
Type - OperationType: SINGLE_SWING_LEFT; ParameterTakesPrecedence: no; Sizeable: no; Material: Peinture - Gris clair
Type - Por-003 9927:Por-003 9927:195816:1 - PanelOperation: SWINGING
Type - Pset_DoorCommon - IsExternal: no
OverallHeight: 2.09 m; OverallWidth: 1.03 m
Pset_DoorCommon - IsExternal: yes; Reference: Por-003 9927
Pset_QuantityTakeOff - Reference: Por-003 9927

# IfcDoor: Por-003, Por-003 9927:Por-003 9927:195825
In: REZ-DE-CHAUSSÉE
Type - OperationType: SINGLE_SWING_LEFT; ParameterTakesPrecedence: no; Sizeable: no; Material: Peinture - Gris clair
Type - Por-003 9927:Por-003 9927:195825:1 - PanelOperation: SWINGING
Type - Pset_DoorCommon - IsExternal: no
OverallHeight: 2.09 m; OverallWidth: 1.03 m
Pset_DoorCommon - Reference: Por-003 9927
Pset_QuantityTakeOff - Reference: Por-003 9927

# IfcDoor: Por-003, Por-003 9927:Por-003 9927:195856
In: REZ-DE-CHAUSSÉE
Type - OperationType: SINGLE_SWING_LEFT; ParameterTakesPrecedence: no; Sizeable: no; Material: Peinture - Gris clair
Type - Por-003 9927:Por-003 9927:195856:1 - PanelOperation: SWINGING
Type - Pset_DoorCommon - IsExternal: no
OverallHeight: 2.09 m; OverallWidth: 1.03 m
Pset_DoorCommon - Reference: Por-003 9927
Pset_QuantityTakeOff - Reference: Por-003 9927

# IfcDoor: Por-003, Por-003 14862:Por-003 14862:195850
In: REZ-DE-CHAUSSÉE
Type - OperationType: SINGLE_SWING_RIGHT; ParameterTakesPrecedence: no; Sizeable: no; Material: Peinture - Anthracite
Type - Por-003 14862:Por-003 14862:195850:1 - PanelOperation: SWINGING
Type - Pset_DoorCommon - IsExternal: no
OverallHeight: 2.09 m; OverallWidth: 1.13 m
Pset_DoorCommon - IsExternal: yes; Reference: Por-003 14862
Pset_QuantityTakeOff - Reference: Por-003 14862

# IfcDoor: Por-003, Por-003 13003:Por-003 13003:195845
In: REZ-DE-CHAUSSÉE
Type - OperationType: SINGLE_SWING_RIGHT; ParameterTakesPrecedence: no; Sizeable: no; Material: Peinture - Gris clair
Type - Por-003 13003:Por-003 13003:195845:1 - PanelOperation: SWINGING
Type - Pset_DoorCommon - IsExternal: no
OverallHeight: 2.09 m; OverallWidth: 1.03 m
Pset_DoorCommon - IsExternal: yes; Reference: Por-003 13003
Pset_QuantityTakeOff - Reference: Por-003 13003

# IfcDoor: Por-004 (2)
In: ÉTAGE
Type - OperationType: DOUBLE_DOOR_SINGLE_SWING; ParameterTakesPrecedence: no; Sizeable: no; Material: Peinture - Gris clair
Type - Por-004 444825:Por-004 444825:198699:1 - PanelOperation: SWINGING
Type - Pset_DoorCommon - IsExternal: no
OverallHeight: 2.44 m; OverallWidth: 1.4 m
Pset_DoorCommon - Reference: Por-004 444825
Pset_QuantityTakeOff - Reference: Por-004 444825
Name (Por-004 444825:Por-004 444825:...)
198699 | Pset_DoorCommon - IsExternal: yes
198700

# IfcDoor: Por-004, Por-004 446802:Por-004 446802:198702
In: ÉTAGE
Type - OperationType: DOUBLE_DOOR_SINGLE_SWING; ParameterTakesPrecedence: no; Sizeable: no; Material: Peinture - Gris clair
Type - Por-004 446802:Por-004 446802:198702:1 - PanelOperation: SWINGING
Type - Pset_DoorCommon - IsExternal: no
OverallHeight: 2.09 m; OverallWidth: 1.65 m
Pset_DoorCommon - IsExternal: yes; Reference: Por-004 446802
Pset_QuantityTakeOff - Reference: Por-004 446802

# IfcDoor: Por-004, Por-004 447233:Por-004 447233:198704
In: ÉTAGE
Type - OperationType: DOUBLE_DOOR_SINGLE_SWING; ParameterTakesPrecedence: no; Sizeable: no; Material: Peinture - Gris clair
Type - Por-004 447233:Por-004 447233:198704:1 - PanelOperation: SWINGING
Type - Pset_DoorCommon - IsExternal: no
OverallHeight: 2.09 m; OverallWidth: 1.65 m
Pset_DoorCommon - IsExternal: yes; Reference: Por-004 447233
Pset_QuantityTakeOff - Reference: Por-004 447233

# IfcDoor: Por-004, Por-004 802047:Por-004 802047:198808
In: ÉTAGE
Type - OperationType: DOUBLE_DOOR_SINGLE_SWING; ParameterTakesPrecedence: no; Sizeable: no; Material: Peinture - Gris clair
Type - Por-004 802047:Por-004 802047:198808:1 - PanelOperation: SWINGING
Type - Pset_DoorCommon - IsExternal: no
OverallHeight: 2.09 m; OverallWidth: 1.53 m
Pset_DoorCommon - IsExternal: yes; Reference: Por-004 802047
Pset_QuantityTakeOff - Reference: Por-004 802047

# IfcDoor: Por-004, Por-004 803945:Por-004 803945:198818
In: ÉTAGE
Type - OperationType: DOUBLE_DOOR_SINGLE_SWING; ParameterTakesPrecedence: no; Sizeable: no; Material: Peinture - Gris clair
Type - Por-004 803945:Por-004 803945:198818:1 - PanelOperation: SWINGING
Type - Pset_DoorCommon - IsExternal: no
OverallHeight: 2.09 m; OverallWidth: 1.53 m
Pset_DoorCommon - IsExternal: yes; Reference: Por-004 803945
Pset_QuantityTakeOff - Reference: Por-004 803945

# IfcDoor: Por-004 (2)
Type - OperationType: SINGLE_SWING_LEFT; ParameterTakesPrecedence: no; Sizeable: no; Material: Peinture - Gris clair
Type - Por-004 25692:Por-004 25692:195933:1 - PanelOperation: SWINGING
Type - Pset_DoorCommon - IsExternal: no
OverallHeight: 2.09 m; OverallWidth: 1.03 m
Pset_DoorCommon - Reference: Por-004 25692
Pset_QuantityTakeOff - Reference: Por-004 25692
Name (Por-004 25692:Por-004 25692:...) | In
195933 | REZ-DE-CHAUSSÉE | Pset_DoorCommon - IsExternal: yes
198753 | ÉTAGE

# IfcDoor: Por-004, Por-004 147422:Por-004 147422:196540
In: REZ-DE-CHAUSSÉE
Type - OperationType: SINGLE_SWING_RIGHT; ParameterTakesPrecedence: no; Sizeable: no; Material: Métal - Acier inoxydable
Type - Por-004 147422:Por-004 147422:196540:1 - PanelOperation: SWINGING
Type - Pset_DoorCommon - IsExternal: no
OverallHeight: 2.05 m; OverallWidth: 1 m
Pset_DoorCommon - IsExternal: yes; Reference: Por-004 147422
Pset_QuantityTakeOff - Reference: Por-004 147422

# IfcDoor: Por-004, Por-004 20814:Por-004 20814:195899
In: REZ-DE-CHAUSSÉE
Type - OperationType: SINGLE_SWING_RIGHT; ParameterTakesPrecedence: no; Sizeable: no; Material: Peinture - Gris clair
Type - Por-004 20814:Por-004 20814:195899:1 - PanelOperation: SWINGING
Type - Pset_DoorCommon - IsExternal: no
OverallHeight: 2.09 m; OverallWidth: 1.03 m
Pset_DoorCommon - IsExternal: yes; Reference: Por-004 20814
Pset_QuantityTakeOff - Reference: Por-004 20814

# IfcDoor: Por-004, Por-004 257092:Por-004 257092:198213
In: ÉTAGE
Type - OperationType: SINGLE_SWING_RIGHT; ParameterTakesPrecedence: no; Sizeable: no; Material: Peinture - Gris clair
Type - Por-004 257092:Por-004 257092:198213:1 - PanelOperation: SWINGING
Type - Pset_DoorCommon - IsExternal: no
OverallHeight: 2.09 m; OverallWidth: 1.03 m
Pset_DoorCommon - IsExternal: yes; Reference: Por-004 257092
Pset_QuantityTakeOff - Reference: Por-004 257092

# IfcDoor: Por-004, Por-004 802370:Por-004 802370:198810
In: ÉTAGE
Type - OperationType: SINGLE_SWING_RIGHT; ParameterTakesPrecedence: no; Sizeable: no; Material: Peinture - Gris clair
Type - Por-004 802370:Por-004 802370:198810:1 - PanelOperation: SWINGING
Type - Pset_DoorCommon - IsExternal: no
OverallHeight: 2.09 m; OverallWidth: 1.03 m
Pset_DoorCommon - IsExternal: yes; Reference: Por-004 802370
Pset_QuantityTakeOff - Reference: Por-004 802370

# IfcDoor: Por-005 (2)
In: REZ-DE-CHAUSSÉE
Type - OperationType: SINGLE_SWING_LEFT; ParameterTakesPrecedence: no; Sizeable: no; Material: Peinture - Gris clair
Type - Por-005 20335:Por-005 20335:195895:1 - PanelOperation: SWINGING
Type - Pset_DoorCommon - IsExternal: no
OverallHeight: 2.09 m; OverallWidth: 1.03 m
Pset_DoorCommon - Reference: Por-005 20335
Pset_QuantityTakeOff - Reference: Por-005 20335
Name (Por-005 20335:Por-005 20335:...)
195895 | Pset_DoorCommon - IsExternal: yes
195898

# IfcDoor: Por-007 (2)
In: REZ-DE-CHAUSSÉE
Type - OperationType: SINGLE_SWING_LEFT; ParameterTakesPrecedence: no; Sizeable: no; Material: Peinture - Gris clair
Type - Por-007 19986:Por-007 19986:195893:1 - PanelOperation: SWINGING
Type - Pset_DoorCommon - IsExternal: no
OverallHeight: 2.09 m; OverallWidth: 1.03 m
Pset_DoorCommon - Reference: Por-007 19986
Pset_QuantityTakeOff - Reference: Por-007 19986
Name (Por-007 19986:Por-007 19986:...)
195893 | Pset_DoorCommon - IsExternal: yes
195903

# IfcFurnishingElement: Symb-0004 (54)
Type - Material: Bois - Chêne clair
Name | In | Reference
Symb-0004 160430:Symb-0004 160430:151174 | REZ-DE-CHAUSSÉE | Symb-0004 160430
Symb-0004 199595:Symb-0004 199595:151261 | REZ-DE-CHAUSSÉE | Symb-0004 199595
Symb-0004 199721:Symb-0004 199721:151268 | REZ-DE-CHAUSSÉE | Symb-0004 199721
Symb-0004 200096:Symb-0004 200096:151275 | REZ-DE-CHAUSSÉE | Symb-0004 200096
Symb-0004 200139:Symb-0004 200139:151282 | REZ-DE-CHAUSSÉE | Symb-0004 200139
Symb-0004 226285:Symb-0004 226285:151342 | REZ-DE-CHAUSSÉE | Symb-0004 226285
Symb-0004 226328:Symb-0004 226328:151349 | REZ-DE-CHAUSSÉE | Symb-0004 226328
Symb-0004 226414:Symb-0004 226414:151398 | REZ-DE-CHAUSSÉE | Symb-0004 226414
Symb-0004 226457:Symb-0004 226457:151405 | REZ-DE-CHAUSSÉE | Symb-0004 226457
Symb-0004 226500:Symb-0004 226500:151412 | REZ-DE-CHAUSSÉE | Symb-0004 226500
Symb-0004 226543:Symb-0004 226543:151419 | REZ-DE-CHAUSSÉE | Symb-0004 226543
Symb-0004 226629:Symb-0004 226629:151468 | REZ-DE-CHAUSSÉE | Symb-0004 226629
Symb-0004 226672:Symb-0004 226672:151475 | REZ-DE-CHAUSSÉE | Symb-0004 226672
Symb-0004 226715:Symb-0004 226715:151482 | REZ-DE-CHAUSSÉE | Symb-0004 226715
Symb-0004 226758:Symb-0004 226758:151489 | REZ-DE-CHAUSSÉE | Symb-0004 226758
Symb-0004 226844:Symb-0004 226844:151538 | REZ-DE-CHAUSSÉE | Symb-0004 226844
Symb-0004 232860:Symb-0004 232860:151587 | REZ-DE-CHAUSSÉE | Symb-0004 232860
Symb-0004 238571:Symb-0004 238571:151594 | REZ-DE-CHAUSSÉE | Symb-0004 238571
Symb-0004 238614:Symb-0004 238614:151601 | REZ-DE-CHAUSSÉE | Symb-0004 238614
Symb-0004 238657:Symb-0004 238657:151608 | REZ-DE-CHAUSSÉE | Symb-0004 238657
Symb-0004 238700:Symb-0004 238700:151615 | REZ-DE-CHAUSSÉE | Symb-0004 238700
Symb-0004 238743:Symb-0004 238743:151622 | REZ-DE-CHAUSSÉE | Symb-0004 238743
Symb-0004 238786:Symb-0004 238786:151629 | REZ-DE-CHAUSSÉE | Symb-0004 238786
Symb-0004 238829:Symb-0004 238829:151636 | REZ-DE-CHAUSSÉE | Symb-0004 238829
Symb-0004 517549:Symb-0004 517549:160942 | ÉTAGE | Symb-0004 517549
Symb-0004 517592:Symb-0004 517592:160949 | ÉTAGE | Symb-0004 517592
Symb-0004 517635:Symb-0004 517635:160956 | ÉTAGE | Symb-0004 517635
Symb-0004 517678:Symb-0004 517678:160963 | ÉTAGE | Symb-0004 517678
Symb-0004 517721:Symb-0004 517721:160970 | ÉTAGE | Symb-0004 517721
Symb-0004 517764:Symb-0004 517764:160977 | ÉTAGE | Symb-0004 517764
Symb-0004 753520:Symb-0004 753520:161170 | ÉTAGE | Symb-0004 753520
Symb-0004 753563:Symb-0004 753563:161177 | ÉTAGE | Symb-0004 753563
Symb-0004 753606:Symb-0004 753606:161184 | ÉTAGE | Symb-0004 753606
Symb-0004 753649:Symb-0004 753649:161191 | ÉTAGE | Symb-0004 753649
Symb-0004 753692:Symb-0004 753692:161198 | ÉTAGE | Symb-0004 753692
Symb-0004 753735:Symb-0004 753735:161205 | ÉTAGE | Symb-0004 753735
Symb-0004 753778:Symb-0004 753778:161212 | ÉTAGE | Symb-0004 753778
Symb-0004 753821:Symb-0004 753821:161219 | ÉTAGE | Symb-0004 753821
Symb-0004 753864:Symb-0004 753864:161226 | ÉTAGE | Symb-0004 753864
Symb-0004 753907:Symb-0004 753907:161233 | ÉTAGE | Symb-0004 753907
Symb-0004 753950:Symb-0004 753950:161240 | ÉTAGE | Symb-0004 753950
Symb-0004 753993:Symb-0004 753993:161247 | ÉTAGE | Symb-0004 753993
Symb-0004 769324:Symb-0004 769324:161335 | ÉTAGE | Symb-0004 769324
Symb-0004 769367:Symb-0004 769367:161342 | ÉTAGE | Symb-0004 769367
Symb-0004 769410:Symb-0004 769410:161349 | ÉTAGE | Symb-0004 769410
Symb-0004 769453:Symb-0004 769453:161356 | ÉTAGE | Symb-0004 769453
Symb-0004 769496:Symb-0004 769496:161363 | ÉTAGE | Symb-0004 769496
Symb-0004 769539:Symb-0004 769539:161370 | ÉTAGE | Symb-0004 769539
Symb-0004 769582:Symb-0004 769582:161377 | ÉTAGE | Symb-0004 769582
Symb-0004 769625:Symb-0004 769625:161384 | ÉTAGE | Symb-0004 769625
Symb-0004 769668:Symb-0004 769668:161391 | ÉTAGE | Symb-0004 769668
Symb-0004 769711:Symb-0004 769711:161398 | ÉTAGE | Symb-0004 769711
Symb-0004 769754:Symb-0004 769754:161405 | ÉTAGE | Symb-0004 769754
Symb-0004 769797:Symb-0004 769797:161412 | ÉTAGE | Symb-0004 769797

# IfcFurnishingElement: Symb-0004 (5)
Type - Material: Bois - Lamellé-collé
Name | In | Reference
Symb-0004 175769:Symb-0004 175769:151181 | REZ-DE-CHAUSSÉE | Symb-0004 175769
Symb-0004 190778:Symb-0004 190778:151191 | REZ-DE-CHAUSSÉE | Symb-0004 190778
Symb-0004 219202:Symb-0004 219202:151303 | REZ-DE-CHAUSSÉE | Symb-0004 219202
Symb-0004 516909:Symb-0004 516909:160861 | ÉTAGE | Symb-0004 516909
Symb-0004 768688:Symb-0004 768688:161254 | ÉTAGE | Symb-0004 768688

# IfcFurnishingElement: Symb-0004 (20)
In: ÉTAGE
Type - Material: Métal - Acier inoxydable
Name | Reference
Symb-0004 487519:Symb-0004 487519:160847 | Symb-0004 487519
Symb-0004 502214:Symb-0004 502214:160854 | Symb-0004 502214
Symb-0004 532459:Symb-0004 532459:160984 | Symb-0004 532459
Symb-0004 547154:Symb-0004 547154:160991 | Symb-0004 547154
Symb-0004 561849:Symb-0004 561849:160998 | Symb-0004 561849
Symb-0004 576544:Symb-0004 576544:161005 | Symb-0004 576544
Symb-0004 591239:Symb-0004 591239:161012 | Symb-0004 591239
Symb-0004 605934:Symb-0004 605934:161019 | Symb-0004 605934
Symb-0004 620629:Symb-0004 620629:161026 | Symb-0004 620629
Symb-0004 635324:Symb-0004 635324:161033 | Symb-0004 635324
Symb-0004 650019:Symb-0004 650019:161040 | Symb-0004 650019
Symb-0004 664714:Symb-0004 664714:161047 | Symb-0004 664714
Symb-0004 679409:Symb-0004 679409:161054 | Symb-0004 679409
Symb-0004 694104:Symb-0004 694104:161061 | Symb-0004 694104
Symb-0004 708799:Symb-0004 708799:161068 | Symb-0004 708799
Symb-0004 723494:Symb-0004 723494:161075 | Symb-0004 723494
Symb-0004 738189:Symb-0004 738189:161082 | Symb-0004 738189
Symb-0004 752884:Symb-0004 752884:161089 | Symb-0004 752884
Symb-0004 784492:Symb-0004 784492:161419 | Symb-0004 784492
Symb-0004 799187:Symb-0004 799187:161426 | Symb-0004 799187

# IfcFurnishingElement: Symb-0004 (8)
Type - Material: Peinture - Blanc brillant
Name | In | Reference
Symb-0004 193880:Symb-0004 193880:151219 | REZ-DE-CHAUSSÉE | Symb-0004 193880
Symb-0004 226371:Symb-0004 226371:151356 | REZ-DE-CHAUSSÉE | Symb-0004 226371
Symb-0004 226586:Symb-0004 226586:151426 | REZ-DE-CHAUSSÉE | Symb-0004 226586
Symb-0004 226801:Symb-0004 226801:151496 | REZ-DE-CHAUSSÉE | Symb-0004 226801
Symb-0004 227149:Symb-0004 227149:151545 | REZ-DE-CHAUSSÉE | Symb-0004 227149
Symb-0004 517502:Symb-0004 517502:160868 | ÉTAGE | Symb-0004 517502
Symb-0004 753477:Symb-0004 753477:161096 | ÉTAGE | Symb-0004 753477
Symb-0004 769281:Symb-0004 769281:161261 | ÉTAGE | Symb-0004 769281

# IfcFurnishingElement: Symb-0004 (5)
In: REZ-DE-CHAUSSÉE
Type - Material: Peinture - Blanc titanium
Name | Reference
Symb-0004 152170:Symb-0004 152170:151097 | Symb-0004 152170
Symb-0004 153277:Symb-0004 153277:151132 | Symb-0004 153277
Symb-0004 154335:Symb-0004 154335:151139 | Symb-0004 154335
Symb-0004 219298:Symb-0004 219298:151311 | Symb-0004 219298
Symb-0004 220271:Symb-0004 220271:151332 | Symb-0004 220271

# IfcFurnishingElement: Symb-0004 (2)
In: REZ-DE-CHAUSSÉE
Type - Material: Peinture - Noir
Name | Reference
Symb-0004 146473:Symb-0004 146473:151018 | Symb-0004 146473
Symb-0004 219341:Symb-0004 219341:151318 | Symb-0004 219341

# IfcFurnishingElement: Symb-0006 (4)
In: REZ-DE-CHAUSSÉE
Type - Material: Peinture - Blanc titanium
Name | Reference
Symb-0006:Symb-0006:151111 | Symb-0006
Symb-0006 154378:Symb-0006 154378:151146 | Symb-0006 154378
Symb-0006 192453:Symb-0006 192453:151205 | Symb-0006 192453
Symb-0006 193378:Symb-0006 193378:151212 | Symb-0006 193378

# IfcFurnishingElement: Symb-0007 (6)
In: REZ-DE-CHAUSSÉE
Type - Material: Peinture - Blanc titanium
Name | Reference
Symb-0007:Symb-0007:151118 | Symb-0007
Symb-0007 153162:Symb-0007 153162:151125 | Symb-0007 153162
Symb-0007 154421:Symb-0007 154421:151153 | Symb-0007 154421
Symb-0007 154507:Symb-0007 154507:151167 | Symb-0007 154507
Symb-0007 190874:Symb-0007 190874:151198 | Symb-0007 190874
Symb-0007 220175:Symb-0007 220175:151325 | Symb-0007 220175

# IfcFurnishingElement: Symb-0008 (6)
In: REZ-DE-CHAUSSÉE
Type - Material: Peinture - Blanc titanium
Name | Reference
Symb-0008:Symb-0008:147965 | Symb-0008
Symb-0008 36225:Symb-0008 36225:148279 | Symb-0008 36225
Symb-0008 36642:Symb-0008 36642:148286 | Symb-0008 36642
Symb-0008 152213:Symb-0008 152213:151104 | Symb-0008 152213
Symb-0008 154464:Symb-0008 154464:151160 | Symb-0008 154464
Symb-0008 202223:Symb-0008 202223:151296 | Symb-0008 202223

# IfcOpeningElement: Opening (147)
Name | In | Reference | sets with these values
MurExt-026:MurExt-026:148080:1 | VS | MurExt-026 | 2
MurExt-026:MurExt-026:148080:2 | VS | MurExt-026 | 2
MurExt-026:MurExt-026:148080:3 | VS | MurExt-026 | 2
MurExt-026:MurExt-026:148080:4 | VS | MurExt-026 | 2
MurExt-026 133538:MurExt-026 133538:150582:1 | VS | MurExt-026 133538 | 2
MurExt-026 133538:MurExt-026 133538:150582:2 | VS | MurExt-026 133538 | 2
MurExt-026 133538:MurExt-026 133538:150582:3 | VS | MurExt-026 133538 | 2
MurExt-026 133538:MurExt-026 133538:150582:4 | VS | MurExt-026 133538 | 2
MurExt-003 | REZ-DE-CHAUSSÉE | Ouverture 15029 | 2
MurExt-011 | REZ-DE-CHAUSSÉE | Ouverture 41451 | 2
MurExt-009 | REZ-DE-CHAUSSÉE | Ouverture 42207 | 2
MurExt-005 | REZ-DE-CHAUSSÉE | Ouverture 43681 | 2
MurExt-021 | REZ-DE-CHAUSSÉE | Ouverture 48003 | 2
MurExt-002 | ÉTAGE | Ouverture 248342 | 2
Toit de base:Toit-01:194951:1 | ÉTAGE | Toit-01 | 2
Toit de base:Toit-01:194951:2 | ÉTAGE | Toit-01 | 2
Toit de base:Toit-01:194951:3 | ÉTAGE | Toit-01 | 2
Toit de base:Toit-01:194951:4 | ÉTAGE | Toit-01 | 2
Toit de base:Toit-01:194951:5 | ÉTAGE | Toit-01 | 2
Toit de base:Toit-01:195052:1 | ÉTAGE | Toit-01 | 2
Toit de base:Toit-01:1559:195108:1 | ÉTAGE | Toit-01:1559 | 2
Toit de base:Toit-01:1559:195108:2 | ÉTAGE | Toit-01:1559 | 2
Toit de base:Toit-01:1559:195108:3 | ÉTAGE | Toit-01:1559 | 2
Toit de base:Toit-01:1559:195108:4 | ÉTAGE | Toit-01:1559 | 2
Toit de base:Toit-01:1559:195108:5 | ÉTAGE | Toit-01:1559 | 2
Toit de base:Toit-01:195231:1 | TOITURE | Toit-01 | 2
Toit de base:Toit-01:1559:195282:1 | TOITURE | Toit-01:1559 | 2
MurExt-003:1 | VS | Struct. - Pierre 300 | 2
Sol:Dalle-007:1417:196896:2 | REZ-DE-CHAUSSÉE | Dalle-007:1417 | 2
Sol:Dalle-007:1417:196896:3 | REZ-DE-CHAUSSÉE | Dalle-007:1417 | 2
Sol:Dalle-007:1417:196896:4 | REZ-DE-CHAUSSÉE | Dalle-007:1417 | 2
Sol:Dalle-007:1417:196896:5 | REZ-DE-CHAUSSÉE | Dalle-007:1417 | 2
Sol:Dalle-006:1526:197000:2 | REZ-DE-CHAUSSÉE | Dalle-006:1526 | 2
Sol:Dalle-006:1526:197011:2 | REZ-DE-CHAUSSÉE | Dalle-006:1526 | 2
Sol:Dalle-006:1526:197022:2 | REZ-DE-CHAUSSÉE | Dalle-006:1526 | 2
Sol:Dalle-006:1526:197033:2 | REZ-DE-CHAUSSÉE | Dalle-006:1526 | 2
Sol:Dalle-007:1417:197051:2 | REZ-DE-CHAUSSÉE | Dalle-007:1417 | 2
Sol:Dalle-007:1417:197051:3 | REZ-DE-CHAUSSÉE | Dalle-007:1417 | 2
Sol:Dalle-004:198082:2 | ÉTAGE | Dalle-004 | 2
Sol:Dalle-007:1542:198097:2 | ÉTAGE | Dalle-007:1542 | 2
Sol:Dalle-007:1542:198097:3 | ÉTAGE | Dalle-007:1542 | 2
Sol:Dalle-004:198122:2 | ÉTAGE | Dalle-004 | 2
Sol:Dalle-009:1567:198373:2 | ÉTAGE | Dalle-009:1567 | 2
Sol:Dalle-009:1567:198373:3 | ÉTAGE | Dalle-009:1567 | 2
Sol:Dalle-009:1567:198373:4 | ÉTAGE | Dalle-009:1567 | 2
Sol:Dalle-009:1567:198373:5 | ÉTAGE | Dalle-009:1567 | 2
Sol:Dalle-009:1567:198373:6 | ÉTAGE | Dalle-009:1567 | 2
Sol:Dalle-009:1567:198373:7 | ÉTAGE | Dalle-009:1567 | 2
Sol:Dalle-009:1567:198373:8 | ÉTAGE | Dalle-009:1567 | 2
Sol:Dalle-009:1567:198373:9 | ÉTAGE | Dalle-009:1567 | 2
Sol:Dalle-009:1567:198373:10 | ÉTAGE | Dalle-009:1567 | 2
Sol:Dalle-009:1567:198373:11 | ÉTAGE | Dalle-009:1567 | 2
Sol:Dalle-009:1567:198373:12 | ÉTAGE | Dalle-009:1567 | 2
Sol:Dalle-009:1567:198373:13 | ÉTAGE | Dalle-009:1567 | 2
Sol:Dalle-009:1570:198465:2 | ÉTAGE | Dalle-009:1570 | 2
Sol:Dalle-009:1570:198465:3 | ÉTAGE | Dalle-009:1570 | 2
Sol:Dalle-009:1570:198465:4 | ÉTAGE | Dalle-009:1570 | 2
Sol:Dalle-009:1570:198465:5 | ÉTAGE | Dalle-009:1570 | 2
Sol:Dalle-009:1570:198465:6 | ÉTAGE | Dalle-009:1570 | 2
Sol:Dalle-009:1570:198465:7 | ÉTAGE | Dalle-009:1570 | 2
Sol:Dalle-009:1570:198465:8 | ÉTAGE | Dalle-009:1570 | 2
Sol:Dalle-009:1570:198465:9 | ÉTAGE | Dalle-009:1570 | 2
Sol:Dalle-009:1570:198465:10 | ÉTAGE | Dalle-009:1570 | 2
Sol:Dalle-009:1570:198465:11 | ÉTAGE | Dalle-009:1570 | 2
Sol:Dalle-009:1570:198465:12 | ÉTAGE | Dalle-009:1570 | 2
Sol:Dalle-009:1570:198465:13 | ÉTAGE | Dalle-009:1570 | 2
Sol:Dalle-009:1570:198465:14 | ÉTAGE | Dalle-009:1570 | 2
Sol:Dalle-009:1570:198465:15 | ÉTAGE | Dalle-009:1570 | 2
Sol:Dalle-009:1570:198465:16 | ÉTAGE | Dalle-009:1570 | 2
Sol:Dalle-009:1570:198465:17 | ÉTAGE | Dalle-009:1570 | 2
Sol:Dalle-009:1570:198465:18 | ÉTAGE | Dalle-009:1570 | 2
Sol:Dalle-009:1570:198465:19 | ÉTAGE | Dalle-009:1570 | 2
Sol:Dalle-009:1567:198587:2 | ÉTAGE | Dalle-009:1567 | 2
Sol:Dalle-009:1567:198587:3 | ÉTAGE | Dalle-009:1567 | 2
Sol:Dalle-009:1567:198587:4 | ÉTAGE | Dalle-009:1567 | 2
Sol:Dalle-009:1567:198587:5 | ÉTAGE | Dalle-009:1567 | 2
Sol:Dalle-009:1567:198587:6 | ÉTAGE | Dalle-009:1567 | 2
Sol:Dalle-009:1570:198614:2 | ÉTAGE | Dalle-009:1570 | 2
Sol:Dalle-009:1570:198614:3 | ÉTAGE | Dalle-009:1570 | 2
Sol:Dalle-009:1570:198614:4 | ÉTAGE | Dalle-009:1570 | 2
Sol:Dalle-009:1570:198614:5 | ÉTAGE | Dalle-009:1570 | 2
Sol:Dalle-009:1570:198614:6 | ÉTAGE | Dalle-009:1570 | 2
Sol:Dalle-004:198961:2 | TOITURE | Dalle-004 | 2
Sol:Dalle-005:1730:199004:2 | TOITURE | Dalle-005:1730 | 2
Sol:Dalle-005:199126:2 | TOITURE | Dalle-005 | 2
4 x MurExt-003 | REZ-DE-CHAUSSÉE
MurExt-006 | REZ-DE-CHAUSSÉE
4 x MurExt-012 | REZ-DE-CHAUSSÉE
MurExt-015 | REZ-DE-CHAUSSÉE
2 x MurExt-018 | REZ-DE-CHAUSSÉE
MurExt-013 | REZ-DE-CHAUSSÉE
MurExt-004 | REZ-DE-CHAUSSÉE
2 x MurExt-007 | REZ-DE-CHAUSSÉE
5 x MurExt-025 | REZ-DE-CHAUSSÉE
2 x MurExt-023 | REZ-DE-CHAUSSÉE
3 x MurExt-010 | REZ-DE-CHAUSSÉE
5 x MurExt-022 | REZ-DE-CHAUSSÉE
10 x MurExt-027 | REZ-DE-CHAUSSÉE
2 x MurExt-005 | REZ-DE-CHAUSSÉE
3 x MurExt-002 | REZ-DE-CHAUSSÉE
2 x MurExt-021 | REZ-DE-CHAUSSÉE
MurExt-014 | ÉTAGE
MurExt-015 | ÉTAGE
2 x MurExt-018 | ÉTAGE
4 x MurExt-007 | ÉTAGE
2 x MurExt-025 | ÉTAGE
MurExt-013 | ÉTAGE
2 x MurExt-016 | ÉTAGE
MurExt-017 | ÉTAGE

# IfcSlab: Dalle-005, Dalle-005:Dalle-005:152281
In: REZ-DE-CHAUSSÉE
Type - PredefinedType: FLOOR; Material: Béton - Brut
Type - Pset_SlabCommon - IsExternal: no
Pset_QuantityTakeOff - Reference: Dalle-005; sets with these values: 2
Pset_SlabCommon - Reference: Dalle-005

# IfcSlab: Dalle-006 (2)
In: VS
Type - PredefinedType: FLOOR; Material: Béton - Brut
Type - Pset_SlabCommon - IsExternal: no
Pset_QuantityTakeOff - sets with these values: 2
Name | Pset_QuantityTakeOff, Reference = Pset_SlabCommon, Reference
Dalle-006:Dalle-006:148438 | Dalle-006
Dalle-006 44348:Dalle-006 44348:148448 | Dalle-006 44348

# IfcSlab: Dalle-006 (4)
Type - PredefinedType: FLOOR; Material: Env. - Herbe brune
Type - Pset_SlabCommon - IsExternal: no
Pset_QuantityTakeOff - sets with these values: 2
Name | In | Pset_QuantityTakeOff, Reference = Pset_SlabCommon, Reference
Dalle-006 133760:Dalle-006 133760:150654 | EDL R+1 | Dalle-006 133760
Dalle-006 287061:Dalle-006 287061:154223 | ÉTAGE | Dalle-006 287061
Dalle-006 287964:Dalle-006 287964:154460 | REZ-DE-CHAUSSÉE | Dalle-006 287964
Dalle-006 288131:Dalle-006 288131:154467 | REZ-DE-CHAUSSÉE | Dalle-006 288131

# IfcSlab: Dalle-006 (2)
Type - PredefinedType: FLOOR
Type - Pset_SlabCommon - IsExternal: no
Pset_QuantityTakeOff - sets with these values: 2
Name | In | Pset_QuantityTakeOff, Reference = Pset_SlabCommon, Reference
Dalle-006 200778:Dalle-006 200778:151289 | REZ-DE-CHAUSSÉE | Dalle-006 200778
Dalle-006 252460:Dalle-006 252460:152241 | ÉTAGE | Dalle-006 252460

# IfcSlab: Dalle-006 252491:Dalle-006 252491, Dalle-006 252491:Dalle-006 252491:152248
In: ÉTAGE
Type - PredefinedType: FLOOR
Type - Pset_SlabCommon - IsExternal: no
Pset_QuantityTakeOff - Reference: Dalle-006 252491; sets with these values: 2
Pset_SlabCommon - Reference: Dalle-006 252491

# IfcSlab: Dalle-008, Dalle-008:Dalle-008:148675
In: REZ-DE-CHAUSSÉE
Type - PredefinedType: FLOOR; Material: Env. - Herbe brune
Type - Pset_SlabCommon - IsExternal: no
Pset_QuantityTakeOff - Reference: Dalle-008; sets with these values: 2
Pset_SlabCommon - Reference: Dalle-008

# IfcSlab: Dalle-009:Dalle-009, Dalle-009:Dalle-009:150935
In: REZ-DE-CHAUSSÉE
Type - PredefinedType: FLOOR; Material: Surface-Blanc
Type - Pset_SlabCommon - IsExternal: no
Pset_QuantityTakeOff - Reference: Dalle-009; sets with these values: 2
Pset_SlabCommon - Reference: Dalle-009

# IfcSlab: Dalle-010 (3)
Type - PredefinedType: FLOOR
Type - Pset_SlabCommon - IsExternal: no
Pset_QuantityTakeOff - sets with these values: 2
Name | In | Pset_QuantityTakeOff, Reference = Pset_SlabCommon, Reference
Dalle-010:Dalle-010:150961 | REZ-DE-CHAUSSÉE | Dalle-010
Dalle-010 143417:Dalle-010 143417:151004 | REZ-DE-CHAUSSÉE | Dalle-010 143417
Dalle-010 442746:Dalle-010 442746:156029 | ÉTAGE | Dalle-010 442746

# IfcSlab: Sol:Dalle-001 (5)
In: ÉTAGE
Type - PredefinedType: FLOOR; Material: Bois - Pin granuleux horizontal 0.85 m
Type - Pset_SlabCommon - IsExternal: no
Pset_QuantityTakeOff - Reference: Dalle-001; sets with these values: 2
Pset_SlabCommon - LoadBearing: no; PitchAngle: 0 deg; Reference: Dalle-001
Name (Sol:Dalle-001:...)
197932
197939
197946
197953
197960

# IfcSlab: Sol:Dalle-001:1532, Sol:Dalle-001:1532:197925
In: ÉTAGE
Type - PredefinedType: FLOOR; Material: Bois - Pin granuleux horizontal 0.15 m
Type - Pset_SlabCommon - IsExternal: no
Pset_QuantityTakeOff - Reference: Dalle-001:1532; sets with these values: 2
Pset_SlabCommon - LoadBearing: no; PitchAngle: 0 deg; Reference: Dalle-001:1532

# IfcSlab: Sol:Dalle-004 (5)
Type - PredefinedType: FLOOR; Material: Appareillage - Pierre taillé 0.3 m
Type - Pset_SlabCommon - IsExternal: no
Pset_QuantityTakeOff - Reference: Dalle-004; sets with these values: 2
Pset_SlabCommon - LoadBearing: no; PitchAngle: 0 deg; Reference: Dalle-004
Name (Sol:Dalle-004:...) | In
196306 | REZ-DE-CHAUSSÉE
196315 | REZ-DE-CHAUSSÉE
198082 | ÉTAGE
198122 | ÉTAGE
198961 | TOITURE

# IfcSlab: Sol:Dalle-004:1414 (2)
In: REZ-DE-CHAUSSÉE
Type - PredefinedType: FLOOR; Material: Appareillage - Pierre taillé 0.15 m
Type - Pset_SlabCommon - IsExternal: no
Pset_QuantityTakeOff - Reference: Dalle-004:1414; sets with these values: 2
Pset_SlabCommon - LoadBearing: no; PitchAngle: 0 deg; Reference: Dalle-004:1414
Name (Sol:Dalle-004:1414:...)
195948
196263
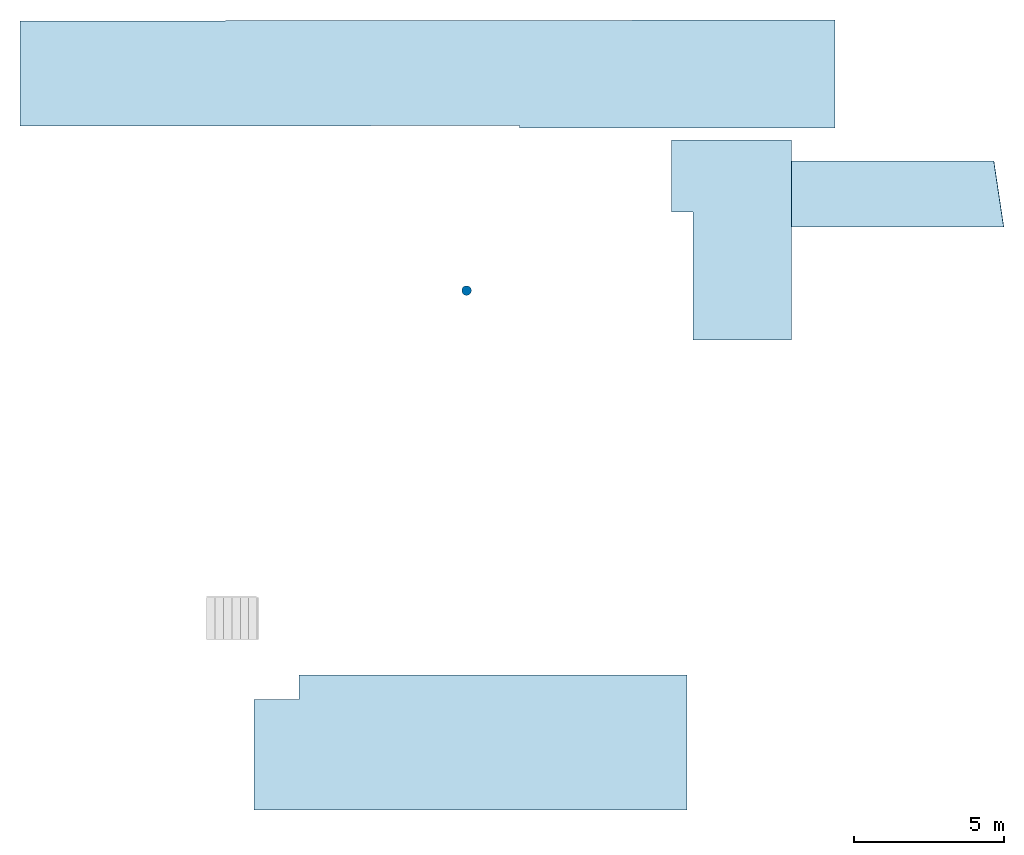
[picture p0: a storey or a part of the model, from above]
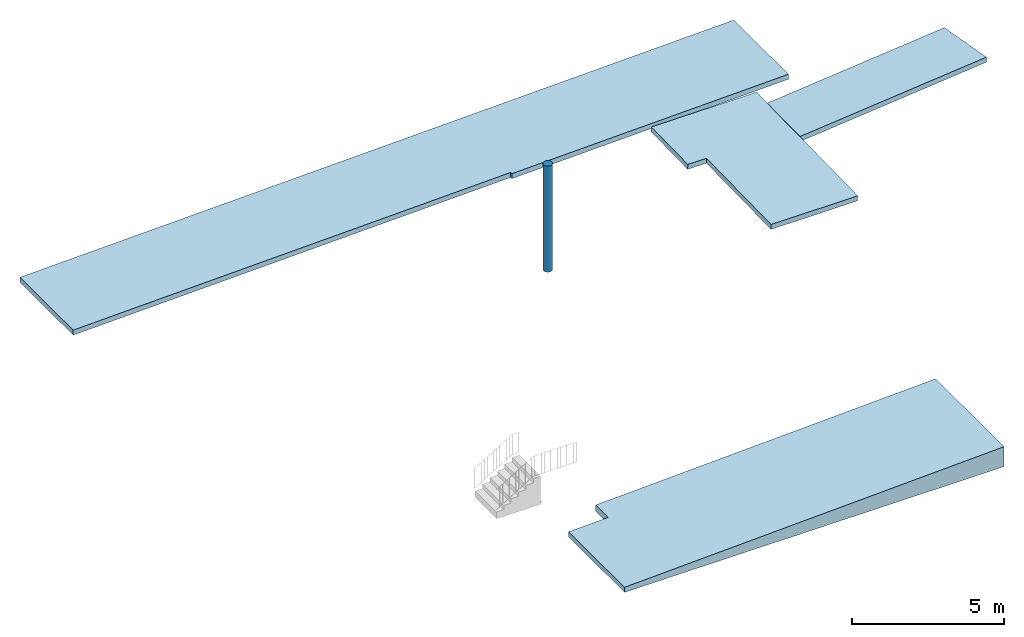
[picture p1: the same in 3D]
Properties of the parts of a building model (IFC2X3), part 2 of 3

# IfcSlab: Sol:Dalle-004:1422, Sol:Dalle-004:1422:196228
In: REZ-DE-CHAUSSÉE
Type - PredefinedType: FLOOR; Material: Appareillage - Pierre taillé 0.22 m
Type - Pset_SlabCommon - IsExternal: no
Pset_QuantityTakeOff - Reference: Dalle-004:1422; sets with these values: 2
Pset_SlabCommon - LoadBearing: no; PitchAngle: 0 deg; Reference: Dalle-004:1422

# IfcSlab: Sol:Dalle-004:1425, Sol:Dalle-004:1425:196274
In: REZ-DE-CHAUSSÉE
Type - PredefinedType: FLOOR; Material: Appareillage - Pierre taillé 0.24 m
Type - Pset_SlabCommon - IsExternal: no
Pset_QuantityTakeOff - Reference: Dalle-004:1425; sets with these values: 2
Pset_SlabCommon - LoadBearing: no; PitchAngle: 0 deg; Reference: Dalle-004:1425

# IfcSlab: Sol:Dalle-005, Sol:Dalle-005:199126
In: TOITURE
Type - PredefinedType: FLOOR; Material: Plâtre - Plaques de plâtre 1 m
Type - Pset_SlabCommon - IsExternal: no
Pset_QuantityTakeOff - Reference: Dalle-005; sets with these values: 2
Pset_SlabCommon - LoadBearing: no; Reference: Dalle-005; PitchAngle: 0 deg

# IfcSlab: Sol:Dalle-005:1552, Sol:Dalle-005:1552:198182
In: ÉTAGE
Type - PredefinedType: FLOOR; Material: Appareillage - Pierre taillé 0.28 m
Type - Pset_SlabCommon - IsExternal: no
Pset_QuantityTakeOff - Reference: Dalle-005:1552; sets with these values: 2
Pset_SlabCommon - LoadBearing: no; PitchAngle: 0 deg; Reference: Dalle-005:1552

# IfcSlab: Sol:Dalle-005:1561, Sol:Dalle-005:1561:198282
In: ÉTAGE
Type - PredefinedType: FLOOR; Material: Plastique - Laminé 0.02 m, Béton - Lissé 0.04 m, Isolation - Polystyrène 0.16 m
Type - Pset_SlabCommon - IsExternal: no
Pset_QuantityTakeOff - Reference: Dalle-005:1561; sets with these values: 2
Pset_SlabCommon - LoadBearing: no; PitchAngle: 0 deg; Reference: Dalle-005:1561

# IfcSlab: Sol:Dalle-005:1562, Sol:Dalle-005:1562:198327
In: ÉTAGE
Type - PredefinedType: FLOOR; Material: Appareillage - Pierre taillé 0.25 m
Type - Pset_SlabCommon - IsExternal: no
Pset_QuantityTakeOff - Reference: Dalle-005:1562; sets with these values: 2
Pset_SlabCommon - LoadBearing: no; PitchAngle: 0 deg; Reference: Dalle-005:1562

# IfcSlab: Sol:Dalle-005:1564, Sol:Dalle-005:1564:198337
In: ÉTAGE
Type - PredefinedType: FLOOR; Material: Carrelage - Faience 0.03 m
Type - Pset_SlabCommon - IsExternal: no
Pset_QuantityTakeOff - Reference: Dalle-005:1564; sets with these values: 2
Pset_SlabCommon - LoadBearing: no; PitchAngle: 0 deg; Reference: Dalle-005:1564

# IfcSlab: Sol:Dalle-005:1569 (2)
In: ÉTAGE
Type - PredefinedType: FLOOR; Material: Béton - Parpaing (Blocs) 0.2 m
Type - Pset_SlabCommon - IsExternal: no
Pset_QuantityTakeOff - Reference: Dalle-005:1569; sets with these values: 2
Pset_SlabCommon - LoadBearing: no; PitchAngle: 0 deg; Reference: Dalle-005:1569
Name (Sol:Dalle-005:1569:...)
198447
198784

# IfcSlab: Sol:Dalle-005:1576, Sol:Dalle-005:1576:198709
In: ÉTAGE
Type - PredefinedType: FLOOR; Material: Appareillage - Pierre taillé 0.1 m
Type - Pset_SlabCommon - IsExternal: no
Pset_QuantityTakeOff - Reference: Dalle-005:1576; sets with these values: 2
Pset_SlabCommon - LoadBearing: no; PitchAngle: 0 deg; Reference: Dalle-005:1576

# IfcSlab: Sol:Dalle-005:1592, Sol:Dalle-005:1592:198757
In: ÉTAGE
Type - PredefinedType: FLOOR; Material: Appareillage - Pierre taillé 0.16 m
Type - Pset_SlabCommon - IsExternal: no
Pset_QuantityTakeOff - Reference: Dalle-005:1592; sets with these values: 2
Pset_SlabCommon - LoadBearing: no; PitchAngle: 0 deg; Reference: Dalle-005:1592

# IfcSlab: Sol:Dalle-005:1705, Sol:Dalle-005:1705:198777
In: ÉTAGE
Type - PredefinedType: FLOOR; Material: Béton - Parpaing (Blocs) 0.12 m
Type - Pset_SlabCommon - IsExternal: no
Pset_QuantityTakeOff - Reference: Dalle-005:1705; sets with these values: 2
Pset_SlabCommon - LoadBearing: no; PitchAngle: 0 deg; Reference: Dalle-005:1705

# IfcSlab: Sol:Dalle-005:1722, Sol:Dalle-005:1722:198802
In: ÉTAGE
Type - PredefinedType: FLOOR; Material: Métal - Zinc 0.04 m
Type - Pset_SlabCommon - IsExternal: no
Pset_QuantityTakeOff - Reference: Dalle-005:1722; sets with these values: 2
Pset_SlabCommon - LoadBearing: no; PitchAngle: 0 deg; Reference: Dalle-005:1722

# IfcSlab: Sol:Dalle-005:1730 (4)
In: TOITURE
Type - PredefinedType: FLOOR; Material: Plâtre - Plaques de plâtre 0.05 m
Type - Pset_SlabCommon - IsExternal: no
Pset_QuantityTakeOff - Reference: Dalle-005:1730; sets with these values: 2
Pset_SlabCommon - LoadBearing: no; PitchAngle: 0 deg; Reference: Dalle-005:1730
Name (Sol:Dalle-005:1730:...)
199004
199057
199137
199144

# IfcSlab: Sol:Dalle-006 (6)
In: REZ-DE-CHAUSSÉE
Type - PredefinedType: FLOOR; Material: Bois - Pin granuleux horizontal 2.35 m
Type - Pset_SlabCommon - IsExternal: no
Pset_QuantityTakeOff - Reference: Dalle-006; sets with these values: 2
Pset_SlabCommon - LoadBearing: no; Reference: Dalle-006; PitchAngle: 0 deg
Name (Sol:Dalle-006:...)
197305
197326
197819
197826
197833
197840

# IfcSlab: Sol:Dalle-006:1397 (2)
In: REZ-DE-CHAUSSÉE
Type - PredefinedType: FLOOR; Material: Env. - Herbe verte 0.25 m
Type - Pset_SlabCommon - IsExternal: no
Pset_QuantityTakeOff - Reference: Dalle-006:1397; sets with these values: 2
Pset_SlabCommon - LoadBearing: no; PitchAngle: 0 deg; Reference: Dalle-006:1397
Name (Sol:Dalle-006:1397:...)
195878
196410

# IfcSlab: Sol:Dalle-006:1416 (3)
In: REZ-DE-CHAUSSÉE
Type - PredefinedType: FLOOR; Material: Bois - Pin granuleux horizontal 1.13 m
Type - Pset_SlabCommon - IsExternal: no
Pset_QuantityTakeOff - Reference: Dalle-006:1416; sets with these values: 2
Pset_SlabCommon - LoadBearing: no; PitchAngle: 0 deg; Reference: Dalle-006:1416
Name (Sol:Dalle-006:1416:...)
196154
196183
196933

# IfcSlab: Sol:Dalle-006:1418 (2)
In: REZ-DE-CHAUSSÉE
Type - PredefinedType: FLOOR; Material: Bois - Pin granuleux horizontal 0.8 m
Type - Pset_SlabCommon - IsExternal: no
Pset_QuantityTakeOff - Reference: Dalle-006:1418; sets with these values: 2
Pset_SlabCommon - LoadBearing: no; PitchAngle: 0 deg; Reference: Dalle-006:1418
Name (Sol:Dalle-006:1418:...)
196172
196567

# IfcSlab: Sol:Dalle-006:1419 (15)
In: REZ-DE-CHAUSSÉE
Type - PredefinedType: FLOOR; Material: Bois - Pin granuleux horizontal 0.06 m
Type - Pset_SlabCommon - IsExternal: no
Pset_QuantityTakeOff - Reference: Dalle-006:1419; sets with these values: 2
Pset_SlabCommon - LoadBearing: no; PitchAngle: 0 deg; Reference: Dalle-006:1419
Name (Sol:Dalle-006:1419:...)
196208
196352
196370
197161
197166
197185
197190
197202
197221
197233
197238
197243
197255
197260
197265

# IfcSlab: Sol:Dalle-006:1420 (13)
In: REZ-DE-CHAUSSÉE
Type - PredefinedType: FLOOR; Material: Bois - Pin granuleux horizontal 0.4 m
Type - Pset_SlabCommon - IsExternal: no
Pset_QuantityTakeOff - Reference: Dalle-006:1420; sets with these values: 2
Pset_SlabCommon - LoadBearing: no; PitchAngle: 0 deg; Reference: Dalle-006:1420
Name (Sol:Dalle-006:1420:...)
196213
196861
196875
197132
197171
197178
197195
197226
197270
197770
197777
197784
197812

# IfcSlab: Sol:Dalle-006:1437, Sol:Dalle-006:1437:196299
In: REZ-DE-CHAUSSÉE
Type - PredefinedType: FLOOR; Material: Appareillage - Pierre taillé 1.06 m
Type - Pset_SlabCommon - IsExternal: no
Pset_QuantityTakeOff - Reference: Dalle-006:1437; sets with these values: 2
Pset_SlabCommon - LoadBearing: no; PitchAngle: 0 deg; Reference: Dalle-006:1437

# IfcSlab: Sol:Dalle-006:1439, Sol:Dalle-006:1439:196330
In: REZ-DE-CHAUSSÉE
Type - PredefinedType: FLOOR; Material: Appareillage - Pierre taillé 0.31 m
Type - Pset_SlabCommon - IsExternal: no
Pset_QuantityTakeOff - Reference: Dalle-006:1439; sets with these values: 2
Pset_SlabCommon - LoadBearing: no; PitchAngle: 0 deg; Reference: Dalle-006:1439

# IfcSlab: Sol:Dalle-006:1522 (7)
In: REZ-DE-CHAUSSÉE
Type - PredefinedType: FLOOR; Material: Bois - Pin granuleux horizontal 2.6 m
Type - Pset_SlabCommon - IsExternal: no
Pset_QuantityTakeOff - Reference: Dalle-006:1522; sets with these values: 2
Pset_SlabCommon - LoadBearing: no; PitchAngle: 0 deg; Reference: Dalle-006:1522
Name (Sol:Dalle-006:1522:...)
196578
196585
196592
196599
196606
196613
196620

# IfcSlab: Sol:Dalle-006:1523 (7)
In: REZ-DE-CHAUSSÉE
Type - PredefinedType: FLOOR; Material: Bois - Pin granuleux horizontal 2.25 m
Type - Pset_SlabCommon - IsExternal: no
Pset_QuantityTakeOff - Reference: Dalle-006:1523; sets with these values: 2
Pset_SlabCommon - LoadBearing: no; PitchAngle: 0 deg; Reference: Dalle-006:1523
Name (Sol:Dalle-006:1523:...)
196725
196732
196739
196746
196753
196760
196830

# IfcSlab: Sol:Dalle-006:1525 (5)
In: REZ-DE-CHAUSSÉE
Type - PredefinedType: FLOOR; Material: Bois - Pin granuleux horizontal 0.76 m
Type - Pset_SlabCommon - IsExternal: no
Pset_QuantityTakeOff - Reference: Dalle-006:1525; sets with these values: 2
Pset_SlabCommon - LoadBearing: no; PitchAngle: 0 deg; Reference: Dalle-006:1525
Name (Sol:Dalle-006:1525:...)
196944
196958
196965
196986
196993

# IfcSlab: Sol:Dalle-006:1526 (4)
In: REZ-DE-CHAUSSÉE
Type - PredefinedType: FLOOR; Material: Bois - Pin granuleux horizontal 0.14 m
Type - Pset_SlabCommon - IsExternal: no
Pset_QuantityTakeOff - Reference: Dalle-006:1526; sets with these values: 2
Pset_SlabCommon - LoadBearing: no; PitchAngle: 0 deg; Reference: Dalle-006:1526
Name (Sol:Dalle-006:1526:...)
197000
197011
197022
197033

# IfcSlab: Sol:Dalle-007, Sol:Dalle-007:198017
In: ÉTAGE
Type - PredefinedType: FLOOR; Material: Appareillage - Pierre taillé 0.29 m
Type - Pset_SlabCommon - IsExternal: no
Pset_QuantityTakeOff - Reference: Dalle-007; sets with these values: 2
Pset_SlabCommon - LoadBearing: no; PitchAngle: 0 deg; Reference: Dalle-007

# IfcSlab: Sol:Dalle-007:1404 (10)
Type - PredefinedType: FLOOR; Material: Isolation - Fibre de verre 0.12 m, Plâtre - Plaques de plâtre 0.02 m
Type - Pset_SlabCommon - IsExternal: no
Pset_QuantityTakeOff - Reference: Dalle-007:1404; sets with these values: 2
Pset_SlabCommon - LoadBearing: no; PitchAngle: 0 deg; Reference: Dalle-007:1404
Name (Sol:Dalle-007:1404:...) | In
195910 | REZ-DE-CHAUSSÉE
195917 | REZ-DE-CHAUSSÉE
196441 | REZ-DE-CHAUSSÉE
196458 | REZ-DE-CHAUSSÉE
196474 | REZ-DE-CHAUSSÉE
196483 | REZ-DE-CHAUSSÉE
196490 | REZ-DE-CHAUSSÉE
196497 | REZ-DE-CHAUSSÉE
198316 | ÉTAGE
198456 | ÉTAGE

# IfcSlab: Sol:Dalle-007:1415 (68)
In: REZ-DE-CHAUSSÉE
Type - PredefinedType: FLOOR; Material: Bois - Pin granuleux horizontal 0.02 m
Type - Pset_SlabCommon - IsExternal: no
Pset_QuantityTakeOff - Reference: Dalle-007:1415; sets with these values: 2
Pset_SlabCommon - LoadBearing: no; PitchAngle: 0 deg; Reference: Dalle-007:1415
Name (Sol:Dalle-007:1415:...)
196147
196544
196560
196627
196634
196641
196648
196655
196662
196669
196676
196683
196690
196697
196704
196711
196718
196767
196774
196781
196788
196795
196802
196809
196816
196823
196837
196844
196868
196882
196889
196919
196926
196951
196972
196979
197044
197139
197147
197154
197207
197214
197248
197277
197284
197291
197298
197312
197319
197333
197340
197347
197354
197361
197368
197375
197749
197756
197763
197791
197798
197805
197847
197854
197861
197868
197875
197882

# IfcSlab: Sol:Dalle-007:1417 (23)
In: REZ-DE-CHAUSSÉE
Type - PredefinedType: FLOOR; Material: Bois - Pin granuleux horizontal 0.03 m
Type - Pset_SlabCommon - IsExternal: no
Pset_QuantityTakeOff - Reference: Dalle-007:1417; sets with these values: 2
Pset_SlabCommon - LoadBearing: no; PitchAngle: 0 deg; Reference: Dalle-007:1417
Name (Sol:Dalle-007:1417:...)
196165
196194
196201
196896
197051
197062
197069
197076
197083
197090
197097
197104
197111
197118
197125
197382
197419
197454
197496
197531
197573
197889
197899

# IfcSlab: Sol:Dalle-007:1501, Sol:Dalle-007:1501:196434
In: REZ-DE-CHAUSSÉE
Type - PredefinedType: FLOOR; Material: Plâtre - Plaques de plâtre 0.38 m
Type - Pset_SlabCommon - IsExternal: no
Pset_QuantityTakeOff - Reference: Dalle-007:1501; sets with these values: 2
Pset_SlabCommon - LoadBearing: no; PitchAngle: 0 deg; Reference: Dalle-007:1501

# IfcSlab: Sol:Dalle-007:1505, Sol:Dalle-007:1505:196518
In: REZ-DE-CHAUSSÉE
Type - PredefinedType: FLOOR; Material: Isolation - Fibre de verre 0.2 m, Plâtre - Plaques de plâtre 0.02 m
Type - Pset_SlabCommon - IsExternal: no
Pset_QuantityTakeOff - Reference: Dalle-007:1505; sets with these values: 2
Pset_SlabCommon - LoadBearing: no; PitchAngle: 0 deg; Reference: Dalle-007:1505

# IfcSlab: Sol:Dalle-007:1542 (4)
Type - PredefinedType: FLOOR; Material: Etanchéité - Membrane souple 0.005 m, Isolation - Fibre de verre 0.095 m, Appareillage - Pierre taillé 0.2 m
Type - Pset_SlabCommon - IsExternal: no
Pset_QuantityTakeOff - Reference: Dalle-007:1542; sets with these values: 2
Pset_SlabCommon - LoadBearing: no; PitchAngle: 0 deg; Reference: Dalle-007:1542
Name (Sol:Dalle-007:1542:...) | In
198010 | ÉTAGE
198097 | ÉTAGE
198954 | TOITURE
198977 | TOITURE

# IfcSlab: Sol:Dalle-008 (20)
In: REZ-DE-CHAUSSÉE
Type - PredefinedType: FLOOR; Material: Bois - Pin granuleux horizontal 0.56 m
Type - Pset_SlabCommon - IsExternal: no
Pset_QuantityTakeOff - Reference: Dalle-008; sets with these values: 2
Pset_SlabCommon - LoadBearing: no; Reference: Dalle-008; PitchAngle: 0 deg
Name (Sol:Dalle-008:...)
197609
197616
197623
197630
197637
197644
197651
197658
197665
197672
197679
197686
197693
197700
197707
197714
197721
197728
197735
197742

# IfcSlab: Sol:Dalle-009 (2)
In: ÉTAGE
Type - PredefinedType: FLOOR; Material: Métal - Fer 0.05 m
Type - Pset_SlabCommon - IsExternal: no
Pset_QuantityTakeOff - Reference: Dalle-009; sets with these values: 2
Pset_SlabCommon - LoadBearing: no; Reference: Dalle-009; PitchAngle: 0 deg
Name (Sol:Dalle-009:...)
198580
198661

# IfcSlab: Sol:Dalle-009:1446, Sol:Dalle-009:1446:196396
In: REZ-DE-CHAUSSÉE
Type - PredefinedType: FLOOR; Material: Peinture - Blanc brillant 0.26 m
Type - Pset_SlabCommon - IsExternal: no
Pset_QuantityTakeOff - Reference: Dalle-009:1446; sets with these values: 2
Pset_SlabCommon - LoadBearing: no; PitchAngle: 0 deg; Reference: Dalle-009:1446

# IfcSlab: Sol:Dalle-009:1495, Sol:Dalle-009:1495:196424
In: REZ-DE-CHAUSSÉE
Type - PredefinedType: FLOOR; Material: Peinture - Blanc brillant 0.31 m
Type - Pset_SlabCommon - IsExternal: no
Pset_QuantityTakeOff - Reference: Dalle-009:1495; sets with these values: 2
Pset_SlabCommon - LoadBearing: no; PitchAngle: 0 deg; Reference: Dalle-009:1495

# IfcSlab: Sol:Dalle-009:1503, Sol:Dalle-009:1503:196467
In: REZ-DE-CHAUSSÉE
Type - PredefinedType: FLOOR; Material: Isolation - Fibre de verre 0.86 m
Type - Pset_SlabCommon - IsExternal: no
Pset_QuantityTakeOff - Reference: Dalle-009:1503; sets with these values: 2
Pset_SlabCommon - LoadBearing: no; PitchAngle: 0 deg; Reference: Dalle-009:1503

# IfcSlab: Sol:Dalle-009:1544 (5)
In: ÉTAGE
Type - PredefinedType: FLOOR; Material: Appareillage - Pierre taillé 0.2 m
Type - Pset_SlabCommon - IsExternal: no
Pset_QuantityTakeOff - Reference: Dalle-009:1544; sets with these values: 2
Pset_SlabCommon - LoadBearing: no; PitchAngle: 0 deg; Reference: Dalle-009:1544
Name (Sol:Dalle-009:1544:...)
198024
198031
198038
198045
198052

# IfcSlab: Sol:Dalle-009:1567 (3)
In: ÉTAGE
Type - PredefinedType: FLOOR; Material: Métal - Fer 0.2 m
Type - Pset_SlabCommon - IsExternal: no
Pset_QuantityTakeOff - Reference: Dalle-009:1567; sets with these values: 2
Pset_SlabCommon - LoadBearing: no; PitchAngle: 0 deg; Reference: Dalle-009:1567
Name (Sol:Dalle-009:1567:...)
198373
198439
198587

# IfcSlab: Sol:Dalle-009:1570 (2)
In: ÉTAGE
Type - PredefinedType: FLOOR; Material: Métal - Fer 0.1 m
Type - Pset_SlabCommon - IsExternal: no
Pset_QuantityTakeOff - Reference: Dalle-009:1570; sets with these values: 2
Pset_SlabCommon - LoadBearing: no; PitchAngle: 0 deg; Reference: Dalle-009:1570
Name (Sol:Dalle-009:1570:...)
198465
198614

# IfcSlab: Sol:Dalle-010, Sol:Dalle-010:198747
In: ÉTAGE
Type - PredefinedType: FLOOR; Material: Isolation - Fibre de verre 0.68 m
Type - Pset_SlabCommon - IsExternal: no
Pset_QuantityTakeOff - Reference: Dalle-010; sets with these values: 2
Pset_SlabCommon - LoadBearing: no; Reference: Dalle-010; PitchAngle: 0 deg

# IfcSlab: Sol:Dalle-010:1502, Sol:Dalle-010:1502:196448
In: REZ-DE-CHAUSSÉE
Type - PredefinedType: FLOOR; Material: Peinture - Blanc brillant 0.4 m, Plâtre - Plaques de plâtre 0.013 m
Type - Pset_SlabCommon - IsExternal: no
Pset_QuantityTakeOff - Reference: Dalle-010:1502; sets with these values: 2
Pset_SlabCommon - LoadBearing: no; PitchAngle: 0 deg; Reference: Dalle-010:1502

# IfcSlab: Sol:Dalle-010:1568, Sol:Dalle-010:1568:198428
In: ÉTAGE
Type - PredefinedType: FLOOR; Material: Plâtre - Plaques de plâtre 1.33 m
Type - Pset_SlabCommon - IsExternal: no
Pset_QuantityTakeOff - Reference: Dalle-010:1568; sets with these values: 2
Pset_SlabCommon - LoadBearing: no; PitchAngle: 0 deg; Reference: Dalle-010:1568

# IfcSlab: Sol:Dalle-010:1572, Sol:Dalle-010:1572:198668
In: ÉTAGE
Type - PredefinedType: FLOOR; Material: Peinture - Blanc brillant 0.33 m
Type - Pset_SlabCommon - IsExternal: no
Pset_QuantityTakeOff - Reference: Dalle-010:1572; sets with these values: 2
Pset_SlabCommon - LoadBearing: no; PitchAngle: 0 deg; Reference: Dalle-010:1572

# IfcSlab: Sol:Dalle-010:1573, Sol:Dalle-010:1573:198677
In: ÉTAGE
Type - PredefinedType: FLOOR; Material: Peinture - Blanc brillant 0.28 m
Type - Pset_SlabCommon - IsExternal: no
Pset_QuantityTakeOff - Reference: Dalle-010:1573; sets with these values: 2
Pset_SlabCommon - LoadBearing: no; PitchAngle: 0 deg; Reference: Dalle-010:1573

# IfcSlab: Toit-01, Toit-01:Toit-01:152015
In: ÉTAGE
Type - PredefinedType: ROOF; Material: Bois - Chêne clair
Type - Pset_SlabCommon - IsExternal: yes; LoadBearing: no
Pset_QuantityTakeOff - Reference: Toit-01; sets with these values: 2
Pset_SlabCommon - Reference: Toit-01

# IfcSlab: Toit-01 (15)
Type - PredefinedType: ROOF; Material: Isolation - Fibre de verre
Type - Pset_SlabCommon - IsExternal: yes; LoadBearing: no
Pset_QuantityTakeOff - sets with these values: 2
Name | In | Pset_QuantityTakeOff, Reference = Pset_SlabCommon, Reference
Toit-01 442954:Toit-01 442954:156043 | ÉTAGE | Toit-01 442954
Toit-01 443125:Toit-01 443125:156052 | REZ-DE-CHAUSSÉE | Toit-01 443125
Toit-01 443288:Toit-01 443288:156059 | REZ-DE-CHAUSSÉE | Toit-01 443288
Toit-01 443451:Toit-01 443451:156066 | REZ-DE-CHAUSSÉE | Toit-01 443451
Toit-01 443614:Toit-01 443614:156073 | REZ-DE-CHAUSSÉE | Toit-01 443614
Toit-01 443777:Toit-01 443777:156080 | REZ-DE-CHAUSSÉE | Toit-01 443777
Toit-01 443940:Toit-01 443940:156087 | REZ-DE-CHAUSSÉE | Toit-01 443940
Toit-01 444103:Toit-01 444103:156094 | REZ-DE-CHAUSSÉE | Toit-01 444103
Toit-01 444266:Toit-01 444266:156101 | REZ-DE-CHAUSSÉE | Toit-01 444266
Toit-01 448454:Toit-01 448454:156153 | ÉTAGE | Toit-01 448454
Toit-01 843311:Toit-01 843311:161930 | TOITURE | Toit-01 843311
Toit-01 843474:Toit-01 843474:161937 | ÉTAGE | Toit-01 843474
Toit-01 843637:Toit-01 843637:161944 | ÉTAGE | Toit-01 843637
Toit-01 843800:Toit-01 843800:161951 | ÉTAGE | Toit-01 843800
Toit-01 843963:Toit-01 843963:161958 | ÉTAGE | Toit-01 843963

# IfcSlab: Toit-01 (2)
In: TOITURE
Type - PredefinedType: ROOF; Material: Peinture - Gris clair
Type - Pset_SlabCommon - IsExternal: yes; LoadBearing: no
Pset_QuantityTakeOff - sets with these values: 2
Name | Pset_QuantityTakeOff, Reference = Pset_SlabCommon, Reference | PitchAngle (deg)
Toit-01 804010:Toit-01 804010:161455 | Toit-01 804010 | 0.0350615
Toit-01 831350:Toit-01 831350:161772 | Toit-01 831350 | 2.00453

# IfcSlab: Toit-01 (2)
In: TOITURE
Type - PredefinedType: ROOF; Material: Peinture - Gris foncé
Type - Pset_SlabCommon - IsExternal: yes; LoadBearing: no
Pset_QuantityTakeOff - sets with these values: 2
Name | Pset_QuantityTakeOff, Reference = Pset_SlabCommon, Reference
Toit-01 824923:Toit-01 824923:161737 | Toit-01 824923
Toit-01 825379:Toit-01 825379:161744 | Toit-01 825379

# IfcSlab: Toit-01 (44)
Type - PredefinedType: ROOF
Type - Pset_SlabCommon - IsExternal: yes; LoadBearing: no
Pset_QuantityTakeOff - sets with these values: 2
Name (Toit de base:Toit-01:...) | In | Material | Pset_QuantityTakeOff, Reference = Pset_SlabCommon, Reference | PitchAngle (deg)
194951 | ÉTAGE | Métal - Zinc 0.00869412 m | Toit-01 | 0
195052 | ÉTAGE | Métal - Zinc 0.00869412 m | Toit-01 | 0
1559:195108 | ÉTAGE | Métal - Zinc 0.05 m | Toit-01:1559 | 0
195231 | TOITURE | Métal - Zinc 0.00869412 m | Toit-01 | 0
1559:195282 | TOITURE | Métal - Zinc 0.05 m | Toit-01:1559 | 0
1421:196224 | REZ-DE-CHAUSSÉE | Transp. - Verre clair (rapide) 0.0173882 m | Toit-01:1421 | 29.6096
1534:197970 | ÉTAGE | Toit - Tuiles françaises rouges 0.271924 m | Toit-01:1534 | 24.9855
1534:197978 | ÉTAGE | Toit - Tuiles françaises rouges 0.271924 m | Toit-01:1534 | 24.9855
1534:197987 | ÉTAGE | Toit - Tuiles françaises rouges 0.271924 m | Toit-01:1534 | 24.9855
1535:197997 | ÉTAGE | Transp. - Verre clair (rapide) 0.0347765 m | Toit-01:1535 | 29.6096
1536:198005 | ÉTAGE | Métal - Fer 0.0997559 m | Toit-01:1536 | 4.5737
1534:198063 | ÉTAGE | Toit - Tuiles françaises rouges 0.271924 m | Toit-01:1534 | 24.9855
1534:198071 | ÉTAGE | Toit - Tuiles françaises rouges 0.271924 m | Toit-01:1534 | 24.9855
1534:198078 | ÉTAGE | Toit - Tuiles françaises rouges 0.271924 m | Toit-01:1534 | 24.9855
1534:198140 | ÉTAGE | Toit - Tuiles françaises rouges 0.271924 m | Toit-01:1534 | 24.9855
1534:198147 | ÉTAGE | Toit - Tuiles françaises rouges 0.271924 m | Toit-01:1534 | 24.9855
1551:198177 | ÉTAGE | Bois - Pin granuleux horizontal 0.0869412 m | Toit-01:1551 | 29.6096
198239 | ÉTAGE | Métal - Zinc 0.00869412 m | Toit-01 | 0
198250 | ÉTAGE | Métal - Zinc 0.00869412 m | Toit-01 | 0
1559:198262 | ÉTAGE | Métal - Zinc 0.05 m | Toit-01:1559 | 0
1566:198364 | ÉTAGE | Métal - Fer 0.0869412 m | Toit-01:1566 | 29.6096
1566:198688 | ÉTAGE | Métal - Fer 0.0869412 m | Toit-01:1566 | 29.6096
1559:198696 | ÉTAGE | Métal - Zinc 0.05 m | Toit-01:1559 | 0
1589:198725 | ÉTAGE | Métal - Zinc 0.0347765 m | Toit-01:1589 | 29.6096
1590:198733 | ÉTAGE | Isolation - Fibre de verre 0.3 m, Plâtre - Plaques de plâtre 0.02 m | Toit-01:1590 | 29.6096
1590:198743 | ÉTAGE | Isolation - Fibre de verre 0.3 m, Plâtre - Plaques de plâtre 0.02 m | Toit-01:1590 | 29.6096
1721:198798 | ÉTAGE | Isolation - Fibre de verre 0.260824 m | Toit-01:1721 | 29.6096
1534:198904 | TOITURE | Toit - Tuiles françaises rouges 0.271924 m | Toit-01:1534 | 24.9855
1534:198912 | TOITURE | Toit - Tuiles françaises rouges 0.271924 m | Toit-01:1534 | 0
1534:198919 | TOITURE | Toit - Tuiles françaises rouges 0.271924 m | Toit-01:1534 | 24.9855
1534:198926 | TOITURE | Toit - Tuiles françaises rouges 0.271924 m | Toit-01:1534 | 24.9855
1589:198939 | TOITURE | Métal - Zinc 0.0347765 m | Toit-01:1589 | 29.6096
1589:198947 | TOITURE | Métal - Zinc 0.0347765 m | Toit-01:1589 | 29.6096
1728:198993 | TOITURE | Métal - Zinc 0.12 m | Toit-01:1728 | 0
1729:199000 | TOITURE | Métal - Zinc 0.0434706 m | Toit-01:1729 | 29.6096
1731:199019 | TOITURE | Métal - Zinc 0.04 m | Toit-01:1731 | 0
1731:199028 | TOITURE | Métal - Zinc 0.04 m | Toit-01:1731 | 0
1731:199035 | TOITURE | Métal - Zinc 0.04 m | Toit-01:1731 | 0
1733:199042 | TOITURE | Transp. - Verre clair (rapide) 0.05 m, Métal - Fer 0.05 m, Isolation - Fibre de verre 0.2 m, Isolation - Fibre de verre 0.1 m, Etanchéité - Membrane souple 0.005 m, Plâtre - Plaques de plâtre 0.055 m | Toit-01:1733 | 15.1096
1559:199054 | TOITURE | Métal - Zinc 0.05 m | Toit-01:1559 | 0
1735:199096 | TOITURE | Métal - Fer 0.05 m | Toit-01:1735 | 15.1096
1729:199106 | TOITURE | Métal - Zinc 0.0434706 m | Toit-01:1729 | 29.6096
1731:199114 | TOITURE | Métal - Zinc 0.04 m | Toit-01:1731 | 0
1736:199123 | TOITURE | Métal - Fer 0.12 m | Toit-01:1736 | 0

# IfcSlab: Toit-02 (3)
In: REZ-DE-CHAUSSÉE
Type - PredefinedType: ROOF; Material: Enduit - Jaune nature
Type - Pset_SlabCommon - IsExternal: yes; LoadBearing: no
Pset_QuantityTakeOff - sets with these values: 2
Name | Pset_QuantityTakeOff, Reference = Pset_SlabCommon, Reference | PitchAngle (deg)
Toit-02:Toit-02:148473 | Toit-02 | 7.53759e-08
Toit-02 45621:Toit-02 45621:148487 | Toit-02 45621 | 1.14576
Toit-02 284151:Toit-02 284151:153135 | Toit-02 284151 | 0.00644469

# IfcSlab: Toit-02, Toit-02 143226:Toit-02 143226:150990
In: REZ-DE-CHAUSSÉE
Type - PredefinedType: ROOF; Material: Métal - Zinc
Type - Pset_SlabCommon - IsExternal: yes; LoadBearing: no
Pset_QuantityTakeOff - Reference: Toit-02 143226; sets with these values: 2
Pset_SlabCommon - Reference: Toit-02 143226; PitchAngle: 1.25125e-07 deg

# IfcSlab: Toit-02 (4)
Type - PredefinedType: ROOF; Material: Sol - Moquette 03
Type - Pset_SlabCommon - IsExternal: yes; LoadBearing: no
Pset_QuantityTakeOff - sets with these values: 2
Name | In | Pset_QuantityTakeOff, Reference = Pset_SlabCommon, Reference
Toit-02 135919:Toit-02 135919:150928 | EDL R+1 | Toit-02 135919
Toit-02 146623:Toit-02 146623:151028 | EDL R+1 | Toit-02 146623 | Pset_SlabCommon - PitchAngle: 0.0114557 deg
Toit-02 240278:Toit-02 240278:151897 | ÉTAGE | Toit-02 240278
Toit-02 453865:Toit-02 453865:158496 | ÉTAGE | Toit-02 453865

# IfcSlab: Toit-02 (3)
In: REZ-DE-CHAUSSÉE
Type - PredefinedType: ROOF
Type - Pset_SlabCommon - IsExternal: yes; LoadBearing: no
Pset_QuantityTakeOff - sets with these values: 2
Name (Toit de base:Toit-02:...) | Material | Pset_QuantityTakeOff, Reference = Pset_SlabCommon, Reference | PitchAngle (deg)
1440:196345 | Env. - Galets 0.0992877 m | Toit-02:1440 | 6.84277
1440:196362 | Env. - Galets 0.0992877 m | Toit-02:1440 | 5.71059
1506:196557 | Isolation - Polystyrène 0.19996 m | Toit-02:1506 | 0

# IfcSlab: Toit-03 (2)
In: VS
Type - PredefinedType: ROOF; Material: Enduit - Jaune nature
Type - Pset_SlabCommon - IsExternal: yes; LoadBearing: no
Pset_QuantityTakeOff - sets with these values: 2
Name | Pset_QuantityTakeOff, Reference = Pset_SlabCommon, Reference | PitchAngle (deg)
Toit-03 39537:Toit-03 39537:148316 | Toit-03 39537 | 0.00286457
Toit-03 39621:Toit-03 39621:148332 | Toit-03 39621 | 0.00644469

# IfcSlab: Toit-03 (8)
Type - PredefinedType: ROOF; Material: Env. - Herbe brune
Type - Pset_SlabCommon - IsExternal: yes; LoadBearing: no
Pset_QuantityTakeOff - sets with these values: 2
Name | In | Pset_QuantityTakeOff, Reference = Pset_SlabCommon, Reference
Toit-03:Toit-03:148303 | REZ-DE-CHAUSSÉE | Toit-03
Toit-03 39735:Toit-03 39735:148354 | VS | Toit-03 39735
Toit-03 40209:Toit-03 40209:148369 | VS | Toit-03 40209
Toit-03 40344:Toit-03 40344:148376 | VS | Toit-03 40344
Toit-03 135242:Toit-03 135242:150913 | VS | Toit-03 135242
Toit-03 146687:Toit-03 146687:151044 | VS | Toit-03 146687
Toit-03 147475:Toit-03 147475:151062 | VS | Toit-03 147475
Toit-03 239654:Toit-03 239654:151643 | VS | Toit-03 239654

# IfcSlab: Toit-03, Toit de base:Toit-03:198772
In: ÉTAGE
Type - PredefinedType: ROOF
Type - Pset_SlabCommon - IsExternal: yes; LoadBearing: no
Material: Env. - Galets 0.198575 m
Pset_QuantityTakeOff - Reference: Toit-03; sets with these values: 2
Pset_SlabCommon - Reference: Toit-03; PitchAngle: 6.84277 deg

# IfcSlab: Toit-04, Toit-04:Toit-04:150920
In: EDL R+1
Type - PredefinedType: ROOF; Material: Sol - Moquette 03
Type - Pset_SlabCommon - IsExternal: yes; LoadBearing: no
Pset_QuantityTakeOff - Reference: Toit-04; sets with these values: 2
Pset_SlabCommon - Reference: Toit-04

# IfcStair: Esc-001:Esc-001 (2)
In: VS
Name (Esc-001:Esc-001:...)
148023 | Material: Béton - Lissé
148023 | Pset_QuantityTakeOff - Reference: Esc-001; Pset_StairCommon - Reference: Esc-001; IsExternal: no

# IfcStair: Esc-002:Esc-002 (2)
In: EDL R+1
Name (Esc-002:Esc-002:...)
150015 | Material: Béton - Brut
150015 | Pset_QuantityTakeOff - Reference: Esc-002; Pset_StairCommon - IsExternal: no; Reference: Esc-002

# IfcWall: MurExt-001, MurExt-001:MurExt-001:147925
In: VS
Type - Pset_WallCommon - IsExternal: yes; LoadBearing: yes
Pset_QuantityTakeOff - Reference: MurExt-001; sets with these values: 2
Pset_WallCommon - Reference: MurExt-001

# IfcWall: MurExt-002, MurExt-002:MurExt-002:148455
In: REZ-DE-CHAUSSÉE
Type - Material: Enduit - Beige nature
Type - Pset_WallCommon - IsExternal: yes; LoadBearing: yes
Pset_QuantityTakeOff - Reference: MurExt-002; sets with these values: 2
Pset_WallCommon - Reference: MurExt-002

# IfcWall: MurExt-003 (2)
Type - Pset_WallCommon - IsExternal: yes; LoadBearing: yes
Pset_QuantityTakeOff - sets with these values: 2
Name | In | Pset_QuantityTakeOff, Reference = Pset_WallCommon, Reference
MurExt-003:MurExt-003:152259 | REZ-DE-CHAUSSÉE | MurExt-003
MurExt-003 838750:MurExt-003 838750:161832 | ÉTAGE | MurExt-003 838750

# IfcWall: MurExt-004 (2)
Type - Pset_WallCommon - IsExternal: yes; LoadBearing: yes
Pset_QuantityTakeOff - sets with these values: 2
Name | In | Pset_QuantityTakeOff, Reference = Pset_WallCommon, Reference
MurExt-004:MurExt-004:151908 | REZ-DE-CHAUSSÉE | MurExt-004
MurExt-004 293430:MurExt-004 293430:155443 | ÉTAGE | MurExt-004 293430

# IfcWall: MurExt-005 (2)
Type - Pset_WallCommon - IsExternal: yes; LoadBearing: yes
Pset_QuantityTakeOff - sets with these values: 2
Name | In | Pset_QuantityTakeOff, Reference = Pset_WallCommon, Reference
MurExt-005:MurExt-005:152270 | REZ-DE-CHAUSSÉE | MurExt-005
MurExt-005 295181:MurExt-005 295181:155483 | ÉTAGE | MurExt-005 295181

# IfcWall: MurExt-006 (3)
Type - Pset_WallCommon - IsExternal: yes; LoadBearing: yes
Pset_QuantityTakeOff - sets with these values: 2
Name | In | Pset_QuantityTakeOff, Reference = Pset_WallCommon, Reference
MurExt-006:MurExt-006:148416 | VS | MurExt-006
MurExt-006 294160:MurExt-006 294160:155470 | ÉTAGE | MurExt-006 294160
MurExt-006 441938:MurExt-006 441938:156016 | ÉTAGE | MurExt-006 441938

# IfcWall: MurExt-007 (2)
In: ÉTAGE
Type - Pset_WallCommon - IsExternal: yes; LoadBearing: yes
Pset_QuantityTakeOff - sets with these values: 2
Name | Pset_QuantityTakeOff, Reference = Pset_WallCommon, Reference
MurExt-007:MurExt-007:155164 | MurExt-007
MurExt-007 445902:MurExt-007 445902:156136 | MurExt-007 445902

# IfcWall: MurExt-008 (2)
Type - Pset_WallCommon - IsExternal: yes; LoadBearing: yes
Pset_QuantityTakeOff - sets with these values: 2
Name | In | Pset_QuantityTakeOff, Reference = Pset_WallCommon, Reference
MurExt-008:MurExt-008:148403 | VS | MurExt-008
MurExt-008 445404:MurExt-008 445404:156123 | ÉTAGE | MurExt-008 445404

# IfcWall: MurExt-009, MurExt-009:MurExt-009:156110
In: ÉTAGE
Type - Pset_WallCommon - IsExternal: yes; LoadBearing: yes
Pset_QuantityTakeOff - Reference: MurExt-009; sets with these values: 2
Pset_WallCommon - Reference: MurExt-009

# IfcWall: MurExt-010, MurExt-010:MurExt-010:148390
In: REZ-DE-CHAUSSÉE
Type - Pset_WallCommon - IsExternal: yes; LoadBearing: yes
Pset_QuantityTakeOff - Reference: MurExt-010; sets with these values: 2
Pset_WallCommon - Reference: MurExt-010

# IfcWall: MurExt-013 (2)
In: REZ-DE-CHAUSSÉE
Type - Pset_WallCommon - IsExternal: yes; LoadBearing: yes
Pset_QuantityTakeOff - sets with these values: 2
Name | Pset_QuantityTakeOff, Reference = Pset_WallCommon, Reference
MurExt-013:MurExt-013:148042 | MurExt-013
MurExt-013 255161:MurExt-013 255161:152390 | MurExt-013 255161

# IfcWall: MurExt-016 (2)
In: REZ-DE-CHAUSSÉE
Type - Pset_WallCommon - IsExternal: yes; LoadBearing: yes
Pset_QuantityTakeOff - sets with these values: 2
Name | Pset_QuantityTakeOff, Reference = Pset_WallCommon, Reference
MurExt-016:MurExt-016:152401 | MurExt-016
MurExt-016 256304:MurExt-016 256304:152412 | MurExt-016 256304

# IfcWall: MurExt-017, MurExt-017:MurExt-017:155429
In: REZ-DE-CHAUSSÉE
Type - Pset_WallCommon - IsExternal: yes; LoadBearing: yes
Pset_QuantityTakeOff - Reference: MurExt-017; sets with these values: 2
Pset_WallCommon - Reference: MurExt-017

# IfcWall: MurExt-018 (4)
Type - Pset_WallCommon - IsExternal: yes; LoadBearing: yes
Pset_QuantityTakeOff - sets with these values: 2
Name | In | Pset_QuantityTakeOff, Reference = Pset_WallCommon, Reference
MurExt-018:MurExt-018:155965 | ÉTAGE | MurExt-018
MurExt-018 804732:MurExt-018 804732:161486 | ÉTAGE | MurExt-018 804732
MurExt-018 806392:MurExt-018 806392:161537 | ÉTAGE | MurExt-018 806392
MurExt-018 810092:MurExt-018 810092:161633 | TOITURE | MurExt-018 810092

# IfcWall: MurExt-019 (6)
Type - Pset_WallCommon - IsExternal: yes; LoadBearing: yes
Pset_QuantityTakeOff - sets with these values: 2
Name | In | Pset_QuantityTakeOff, Reference = Pset_WallCommon, Reference
MurExt-019:MurExt-019:155976 | REZ-DE-CHAUSSÉE | MurExt-019
MurExt-019 805376:MurExt-019 805376:161508 | ÉTAGE | MurExt-019 805376
MurExt-019 807187:MurExt-019 807187:161610 | TOITURE | MurExt-019 807187
MurExt-019 812434:MurExt-019 812434:161652 | TOITURE | MurExt-019 812434
MurExt-019 825486:MurExt-019 825486:161751 | TOITURE | MurExt-019 825486
MurExt-019 831445:MurExt-019 831445:161786 | TOITURE | MurExt-019 831445

# IfcWall: MurExt-020 (5)
Type - Pset_WallCommon - IsExternal: yes; LoadBearing: yes
Pset_QuantityTakeOff - sets with these values: 2
Name | In | Pset_QuantityTakeOff, Reference = Pset_WallCommon, Reference
MurExt-020:MurExt-020:155985 | ÉTAGE | MurExt-020
MurExt-020 805178:MurExt-020 805178:161497 | ÉTAGE | MurExt-020 805178
MurExt-020 805497:MurExt-020 805497:161517 | TOITURE | MurExt-020 805497
MurExt-020 805722:MurExt-020 805722:161528 | ÉTAGE | MurExt-020 805722
MurExt-020 816982:MurExt-020 816982:161671 | TOITURE | MurExt-020 816982

# IfcWall: MurExt-021 (4)
Type - Pset_WallCommon - IsExternal: yes; LoadBearing: yes
Pset_QuantityTakeOff - sets with these values: 2
Name | In | Pset_QuantityTakeOff, Reference = Pset_WallCommon, Reference
MurExt-021:MurExt-021:148462 | REZ-DE-CHAUSSÉE | MurExt-021
MurExt-021 147586:MurExt-021 147586:151076 | REZ-DE-CHAUSSÉE | MurExt-021 147586
MurExt-021 300629:MurExt-021 300629:155996 | REZ-DE-CHAUSSÉE | MurExt-021 300629
MurExt-021 819415:MurExt-021 819415:161690 | TOITURE | MurExt-021 819415

# IfcWall: MurExt-026 (3)
Type - Pset_WallCommon - IsExternal: yes; LoadBearing: yes
Pset_QuantityTakeOff - sets with these values: 2
Name | In | Pset_QuantityTakeOff, Reference = Pset_WallCommon, Reference
MurExt-026:MurExt-026:148080 | VS | MurExt-026
MurExt-026 84420:MurExt-026 84420:149752 | REZ-DE-CHAUSSÉE | MurExt-026 84420
MurExt-026 133538:MurExt-026 133538:150582 | VS | MurExt-026 133538

# IfcWall: zz (3)
In: TOITURE
Type - Pset_WallCommon - IsExternal: yes; LoadBearing: yes
Pset_QuantityTakeOff - sets with these values: 2
Name | Pset_QuantityTakeOff, Reference = Pset_WallCommon, Reference
zz:zz:161819 | zz
zz 839115:zz 839115:161845 | zz 839115
zz 842140:zz 842140:161868 | zz 842140

# IfcWallStandardCase: Mur de base:ABA ITE 140 + enduit 160 (30)
Type - PredefinedType: STANDARD; Material: Enduit - Jaune nature 0.02 m, Isolation - Fibre de verre 0.14 m
Type - Pset_WallCommon - IsExternal: yes
Pset_QuantityTakeOff - Reference: ABA ITE 140 + enduit 160; sets with these values: 2
Pset_WallCommon - LoadBearing: yes; ExtendToStructure: no; Reference: ABA ITE 140 + enduit 160
Name | In
MurExt-011 | REZ-DE-CHAUSSÉE
MurExt-009 | REZ-DE-CHAUSSÉE
MurExt-005 | REZ-DE-CHAUSSÉE
MurExt-002 | ÉTAGE
3 x MurExt-012 | REZ-DE-CHAUSSÉE
2 x MurExt-013 | REZ-DE-CHAUSSÉE
MurExt-018 | REZ-DE-CHAUSSÉE
2 x MurExt-017 | REZ-DE-CHAUSSÉE
MurExt-016 | REZ-DE-CHAUSSÉE
2 x MurExt-015 | REZ-DE-CHAUSSÉE
MurExt-014 | REZ-DE-CHAUSSÉE
MurExt-007 | REZ-DE-CHAUSSÉE
MurExt-004 | REZ-DE-CHAUSSÉE
MurExt-022 | REZ-DE-CHAUSSÉE
MurExt-019 | REZ-DE-CHAUSSÉE
3 x MurExt-008 | ÉTAGE
MurExt-016 | ÉTAGE
MurExt-015 | ÉTAGE
MurExt-014 | ÉTAGE
2 x MurExt-006 | ÉTAGE
MurExt-007 | ÉTAGE
MurExt-003 | ÉTAGE

# IfcWallStandardCase: Mur de base:ABA ITE enduit soubassements 62 (4)
In: REZ-DE-CHAUSSÉE
Type - PredefinedType: STANDARD; Material: Enduit - Jaune nature 0.022 m, Isolation - Fibre de verre 0.04 m
Type - Pset_WallCommon - IsExternal: yes
Pset_QuantityTakeOff - Reference: ABA ITE enduit soubassements 62; sets with these values: 2
Pset_WallCommon - LoadBearing: yes; ExtendToStructure: no; Reference: ABA ITE enduit soubassements 62
Name
MurExt-022
MurExt-023
2 x MurExt-024

# IfcWallStandardCase: Mur de base:ABA MOB ITE bardage 330 (6)
Type - PredefinedType: STANDARD; Material: Métal - Fer 0.037 m, Air - Vide d'air 0.035 m, Isolation - Fibre de verre 0.04 m, Isolation - Fibre de verre 0.145 m, Bois - Panneaux de particules 0.012 m, Air - Vide d'air 0.048 m, Plâtre - Plaques de plâtre 0.013 m
Type - Pset_WallCommon - IsExternal: yes
Pset_QuantityTakeOff - Reference: ABA MOB ITE bardage 330; sets with these values: 2
Pset_WallCommon - LoadBearing: yes; ExtendToStructure: no; Reference: ABA MOB ITE bardage 330
Name | In
MurExt-010 | REZ-DE-CHAUSSÉE
MurExt-003 | REZ-DE-CHAUSSÉE
MurExt-002 | REZ-DE-CHAUSSÉE
MurExt-020 | ÉTAGE
MurExt-021 | ÉTAGE
MurExt-010 | ÉTAGE

# IfcWallStandardCase: Mur de base:ABA MOB ITE enduit 280 (5)
In: ÉTAGE
Type - PredefinedType: STANDARD; Material: Enduit - Jaune nature 0.022 m, Isolation - Fibre de verre 0.04 m, Isolation - Fibre de verre 0.145 m, Bois - Panneaux de particules 0.012 m, Air - Vide d'air 0.048 m, Plâtre - Plaques de plâtre 0.013 m
Type - Pset_WallCommon - IsExternal: yes
Pset_QuantityTakeOff - Reference: ABA MOB ITE enduit 280; sets with these values: 2
Pset_WallCommon - LoadBearing: yes; ExtendToStructure: no; Reference: ABA MOB ITE enduit 280
Name
MurExt-022
MurExt-017
MurExt-018
MurExt-019
MurExt-021

# IfcWallStandardCase: Mur de base:ABA MOB ITI bardage 350 (8)
In: REZ-DE-CHAUSSÉE
Type - PredefinedType: STANDARD; Material: Bois - Pin granuleux horizontal 0.032 m, Air - Vide d'air 0.054 m, Bois - Panneaux de particules 0.022 m, Isolation - Fibre de verre 0.12 m, Bois - Panneaux de particules 0.022 m, Isolation - Fibre de verre 0.087 m, Plâtre - Plaques de plâtre 0.013 m
Type - Pset_WallCommon - IsExternal: yes
Pset_QuantityTakeOff - Reference: ABA MOB ITI bardage 350; sets with these values: 2
Pset_WallCommon - LoadBearing: yes; ExtendToStructure: no; Reference: ABA MOB ITI bardage 350
Name
6 x MurExt-005
2 x MurExt-012

# IfcWallStandardCase: Mur de base:ABA MOB ITI costière 270 (2)
In: REZ-DE-CHAUSSÉE
Type - PredefinedType: STANDARD; Material: Bois - Pin granuleux horizontal 0.02 m, Bois - Panneaux de particules 0.0125 m, Isolation - Fibre de verre 0.145 m, Bois - Panneaux de particules 0.0125 m, Isolation - Fibre de verre 0.067 m, Plâtre - Plaques de plâtre 0.013 m
Type - Pset_WallCommon - IsExternal: yes
Pset_QuantityTakeOff - Reference: ABA MOB ITI costière 270; sets with these values: 2
Pset_WallCommon - LoadBearing: yes; ExtendToStructure: no; Reference: ABA MOB ITI costière 270

# IfcWallStandardCase: Mur de base:ABA MOB bardage 250 (5)
In: REZ-DE-CHAUSSÉE
Type - PredefinedType: STANDARD; Material: Bois - Pin granuleux horizontal 0.032 m, Air - Vide d'air 0.041 m, Bois - Panneaux de particules 0.022 m, Isolation - Fibre de verre 0.12 m, Bois - Panneaux de particules 0.022 m, Plâtre - Plaques de plâtre 0.013 m
Type - Pset_WallCommon - IsExternal: yes
Pset_QuantityTakeOff - Reference: ABA MOB bardage 250; sets with these values: 2
Pset_WallCommon - LoadBearing: yes; ExtendToStructure: no; Reference: ABA MOB bardage 250
Name
2 x MurExt-003
MurExt-004
MurExt-010
MurExt-002

# IfcWallStandardCase: Mur de base:ABA MOB costières 190, MurExt-005
In: REZ-DE-CHAUSSÉE
Type - PredefinedType: STANDARD; Material: Métal - Zinc 0.02 m, Bois - Panneaux de particules 0.012 m, Isolation - Fibre de verre 0.146 m, Bois - Panneaux de particules 0.012 m
Type - Pset_WallCommon - IsExternal: yes
Pset_QuantityTakeOff - Reference: ABA MOB costières 190; sets with these values: 2
Pset_WallCommon - LoadBearing: yes; ExtendToStructure: no; Reference: ABA MOB costières 190

# IfcWallStandardCase: Mur de base:ABA cloison 10cm 100 (8)
In: ÉTAGE
Type - PredefinedType: STANDARD; Material: Plâtre - Plaques de plâtre 0.013 m, Plâtre - Plaques de plâtre 0.013 m, Isolation - Fibre de verre 0.048 m, Plâtre - Plaques de plâtre 0.013 m, Plâtre - Plaques de plâtre 0.013 m
Type - Pset_WallCommon - IsExternal: yes
Pset_QuantityTakeOff - Reference: ABA cloison 10cm 100; sets with these values: 2
Pset_WallCommon - LoadBearing: yes; ExtendToStructure: no; Reference: ABA cloison 10cm 100
Name
MurExt-015
3 x MurExt-016
MurExt-014
MurExt-018
MurExt-019
MurExt-017

# IfcWallStandardCase: Mur de base:ABA cloison 5cm 50 (2)
In: ÉTAGE
Type - PredefinedType: STANDARD; Material: Plâtre - Plaques de plâtre 0.013 m, Isolation - Fibre de verre 0.024 m, Plâtre - Plaques de plâtre 0.013 m
Type - Pset_WallCommon - IsExternal: yes
Pset_QuantityTakeOff - Reference: ABA cloison 5cm 50; sets with these values: 2
Pset_WallCommon - LoadBearing: yes; ExtendToStructure: no; Reference: ABA cloison 5cm 50
Name
MurExt-012
MurExt-013

# IfcWallStandardCase: Mur de base:ABA cloison 7cm 70 (17)
Type - PredefinedType: STANDARD; Material: Plâtre - Plaques de plâtre 0.013 m, Isolation - Fibre de verre 0.044 m, Plâtre - Plaques de plâtre 0.013 m
Type - Pset_WallCommon - IsExternal: yes
Pset_QuantityTakeOff - Reference: ABA cloison 7cm 70; sets with these values: 2
Pset_WallCommon - LoadBearing: yes; ExtendToStructure: no; Reference: ABA cloison 7cm 70
Name | In
4 x MurExt-025 | REZ-DE-CHAUSSÉE
MurExt-023 | REZ-DE-CHAUSSÉE
MurExt-022 | REZ-DE-CHAUSSÉE
MurExt-012 | ÉTAGE
MurExt-013 | ÉTAGE
MurExt-014 | ÉTAGE
2 x MurExt-017 | ÉTAGE
3 x MurExt-025 | ÉTAGE
MurExt-016 | ÉTAGE
2 x MurExt-018 | ÉTAGE

# IfcWallStandardCase: Mur de base:ABA doublage 10cm 100 (2)
In: REZ-DE-CHAUSSÉE
Type - PredefinedType: STANDARD; Material: Plâtre - Plaques de plâtre 0.013 m, Isolation - Fibre de verre 0.087 m
Type - Pset_WallCommon - IsExternal: yes
Pset_QuantityTakeOff - Reference: ABA doublage 10cm 100; sets with these values: 2
Pset_WallCommon - LoadBearing: yes; ExtendToStructure: no; Reference: ABA doublage 10cm 100

# IfcWallStandardCase: Mur de base:ABA doublage 14cm 140 (7)
In: REZ-DE-CHAUSSÉE
Type - PredefinedType: STANDARD; Material: Plâtre - Plaques de plâtre 0.013 m, Isolation - Fibre de verre 0.127 m
Type - Pset_WallCommon - IsExternal: yes
Pset_QuantityTakeOff - Reference: ABA doublage 14cm 140; sets with these values: 2
Pset_WallCommon - LoadBearing: yes; ExtendToStructure: no; Reference: ABA doublage 14cm 140
Name
MurExt-023
3 x MurExt-026
MurExt-025
2 x MurExt-024

# IfcWallStandardCase: Mur de base:ABA doublage 7cm 70 (2)
Type - PredefinedType: STANDARD; Material: Plâtre - Plaques de plâtre 0.013 m, Isolation - Fibre de verre 0.057 m
Type - Pset_WallCommon - IsExternal: yes
Pset_QuantityTakeOff - Reference: ABA doublage 7cm 70; sets with these values: 2
Pset_WallCommon - LoadBearing: yes; ExtendToStructure: no; Reference: ABA doublage 7cm 70
Name | In
MurExt-025 | REZ-DE-CHAUSSÉE
MurExt-017 | ÉTAGE

# IfcWallStandardCase: Mur de base:Bois - Massif 01 140 (2)
Type - PredefinedType: STANDARD; Material: Bois - Pin granuleux horizontal 0.14 m
Type - Pset_WallCommon - IsExternal: yes
Pset_QuantityTakeOff - Reference: Bois - Massif 01 140; sets with these values: 2
Pset_WallCommon - LoadBearing: yes; ExtendToStructure: no; Reference: Bois - Massif 01 140
Name | In
MurExt-007 | REZ-DE-CHAUSSÉE
MurExt-007 | ÉTAGE

# IfcWallStandardCase: Mur de base:Finition ext - Fibre-ciment 1000 (3)
Type - PredefinedType: STANDARD; Material: Peinture - Beige sable 1 m
Type - Pset_WallCommon - IsExternal: yes
Pset_QuantityTakeOff - Reference: Finition ext - Fibre-ciment 1000; sets with these values: 2
Pset_WallCommon - LoadBearing: yes; ExtendToStructure: no; Reference: Finition ext - Fibre-ciment 1000
Name | In
MurExt-021 | REZ-DE-CHAUSSÉE
MurExt-022 | REZ-DE-CHAUSSÉE
MurExt-021 | ÉTAGE

# IfcWallStandardCase: Mur de base:Finition ext - Fibre-ciment 500 (3)
In: REZ-DE-CHAUSSÉE
Type - PredefinedType: STANDARD; Material: Peinture - Beige sable 0.5 m
Type - Pset_WallCommon - IsExternal: yes
Pset_QuantityTakeOff - Reference: Finition ext - Fibre-ciment 500; sets with these values: 2
Pset_WallCommon - LoadBearing: yes; ExtendToStructure: no; Reference: Finition ext - Fibre-ciment 500
Name
MurExt-022
2 x MurExt-021

# IfcWallStandardCase: Mur de base:Isolation - Laine de verre 100 (2)
In: REZ-DE-CHAUSSÉE
Type - PredefinedType: STANDARD; Material: Isolation - Fibre de verre 0.1 m
Type - Pset_WallCommon - IsExternal: yes
Pset_QuantityTakeOff - Reference: Isolation - Laine de verre 100; sets with these values: 2
Pset_WallCommon - LoadBearing: yes; ExtendToStructure: no; Reference: Isolation - Laine de verre 100

# IfcWallStandardCase: Mur de base:Métal - Fer 10, MurExt-026
In: ÉTAGE
Type - PredefinedType: STANDARD; Material: Métal - Fer 0.01 m
Type - Pset_WallCommon - IsExternal: yes
Pset_QuantityTakeOff - Reference: Métal - Fer 10; sets with these values: 2
Pset_WallCommon - LoadBearing: yes; ExtendToStructure: no; Reference: Métal - Fer 10

# IfcWallStandardCase: Mur de base:Métal - Fer 100 (4)
In: ÉTAGE
Type - PredefinedType: STANDARD; Material: Métal - Fer 0.1 m
Type - Pset_WallCommon - IsExternal: yes
Pset_QuantityTakeOff - Reference: Métal - Fer 100; sets with these values: 2
Pset_WallCommon - LoadBearing: yes; ExtendToStructure: no; Reference: Métal - Fer 100
Name
MurExt-016
MurExt-015
MurExt-014
MurExt-013

# IfcWallStandardCase: Mur de base:Métal - Fer 20, MurExt-026
In: ÉTAGE
Type - PredefinedType: STANDARD; Material: Métal - Fer 0.02 m
Type - Pset_WallCommon - IsExternal: yes
Pset_QuantityTakeOff - Reference: Métal - Fer 20; sets with these values: 2
Pset_WallCommon - LoadBearing: yes; ExtendToStructure: no; Reference: Métal - Fer 20

# IfcWallStandardCase: Mur de base:Métal - Fer 50 (3)
In: REZ-DE-CHAUSSÉE
Type - PredefinedType: STANDARD; Material: Métal - Fer 0.05 m
Type - Pset_WallCommon - IsExternal: yes
Pset_QuantityTakeOff - Reference: Métal - Fer 50; sets with these values: 2
Pset_WallCommon - LoadBearing: yes; ExtendToStructure: no; Reference: Métal - Fer 50
Name
MurExt-011
MurExt-013
MurExt-014

# IfcWallStandardCase: Mur de base:Métal - Fer 70 (4)
In: ÉTAGE
Type - PredefinedType: STANDARD; Material: Métal - Fer 0.07 m
Type - Pset_WallCommon - IsExternal: yes
Pset_QuantityTakeOff - Reference: Métal - Fer 70; sets with these values: 2
Pset_WallCommon - LoadBearing: yes; ExtendToStructure: no; Reference: Métal - Fer 70
Name
MurExt-017
MurExt-018
MurExt-019
MurExt-020

# IfcWallStandardCase: Mur de base:Struct. - Béton 80 (3)
In: REZ-DE-CHAUSSÉE
Type - PredefinedType: STANDARD; Material: Béton - Lissé 0.08 m
Type - Pset_WallCommon - IsExternal: yes
Pset_QuantityTakeOff - Reference: Struct. - Béton 80; sets with these values: 2
Pset_WallCommon - LoadBearing: yes; ExtendToStructure: no; Reference: Struct. - Béton 80

# IfcWallStandardCase: Mur de base:Struct. - Parpaing béton 100 (2)
In: REZ-DE-CHAUSSÉE
Type - PredefinedType: STANDARD; Material: Béton - Parpaing (Blocs) 0.1 m
Type - Pset_WallCommon - IsExternal: yes
Pset_QuantityTakeOff - Reference: Struct. - Parpaing béton 100; sets with these values: 2
Pset_WallCommon - LoadBearing: yes; ExtendToStructure: no; Reference: Struct. - Parpaing béton 100

# IfcWallStandardCase: Mur de base:Struct. - Parpaing béton 130 (4)
In: REZ-DE-CHAUSSÉE
Type - PredefinedType: STANDARD; Material: Béton - Parpaing (Blocs) 0.13 m
Type - Pset_WallCommon - IsExternal: yes
Pset_QuantityTakeOff - Reference: Struct. - Parpaing béton 130; sets with these values: 2
Pset_WallCommon - LoadBearing: yes; ExtendToStructure: no; Reference: Struct. - Parpaing béton 130
Name
2 x MurExt-021
MurExt-022
MurExt-023

# IfcWallStandardCase: Mur de base:Struct. - Parpaing béton 200 (14)
Type - PredefinedType: STANDARD; Material: Béton - Parpaing (Blocs) 0.2 m
Type - Pset_WallCommon - IsExternal: yes
Pset_QuantityTakeOff - Reference: Struct. - Parpaing béton 200; sets with these values: 2
Pset_WallCommon - LoadBearing: yes; ExtendToStructure: no; Reference: Struct. - Parpaing béton 200
Name | In
6 x MurExt-021 | REZ-DE-CHAUSSÉE
MurExt-024 | REZ-DE-CHAUSSÉE
MurExt-023 | REZ-DE-CHAUSSÉE
6 x MurExt-021 | ÉTAGE

# IfcWallStandardCase: Mur de base:Struct. - Parpaing béton 250, MurExt-021
In: REZ-DE-CHAUSSÉE
Type - PredefinedType: STANDARD; Material: Béton - Parpaing (Blocs) 0.25 m
Type - Pset_WallCommon - IsExternal: yes
Pset_QuantityTakeOff - Reference: Struct. - Parpaing béton 250; sets with these values: 2
Pset_WallCommon - LoadBearing: yes; ExtendToStructure: no; Reference: Struct. - Parpaing béton 250

# IfcWallStandardCase: Mur de base:Struct. - Parpaing béton 400, MurExt-021
In: ÉTAGE
Type - PredefinedType: STANDARD; Material: Béton - Parpaing (Blocs) 0.4 m
Type - Pset_WallCommon - IsExternal: yes
Pset_QuantityTakeOff - Reference: Struct. - Parpaing béton 400; sets with these values: 2
Pset_WallCommon - LoadBearing: yes; ExtendToStructure: no; Reference: Struct. - Parpaing béton 400

# IfcWallStandardCase: Mur de base:Struct. - Pierre 100 (22)
Type - PredefinedType: STANDARD; Material: Appareillage - Pierre taillé 0.1 m
Type - Pset_WallCommon - IsExternal: yes
Pset_QuantityTakeOff - Reference: Struct. - Pierre 100; sets with these values: 2
Pset_WallCommon - LoadBearing: yes; ExtendToStructure: no; Reference: Struct. - Pierre 100
Name | In
MurExt-016 | REZ-DE-CHAUSSÉE
MurExt-017 | REZ-DE-CHAUSSÉE
MurExt-018 | REZ-DE-CHAUSSÉE
MurExt-019 | REZ-DE-CHAUSSÉE
8 x MurExt-004 | REZ-DE-CHAUSSÉE
3 x MurExt-003 | REZ-DE-CHAUSSÉE
MurExt-021 | ÉTAGE
2 x MurExt-004 | ÉTAGE
MurExt-018 | ÉTAGE
MurExt-019 | ÉTAGE
MurExt-020 | ÉTAGE
MurExt-003 | ÉTAGE

# IfcWallStandardCase: Mur de base:Struct. - Pierre 140, MurExt-012
In: REZ-DE-CHAUSSÉE
Type - PredefinedType: STANDARD; Material: Appareillage - Pierre taillé 0.14 m
Type - Pset_WallCommon - IsExternal: yes
Pset_QuantityTakeOff - Reference: Struct. - Pierre 140; sets with these values: 2
Pset_WallCommon - LoadBearing: yes; ExtendToStructure: no; Reference: Struct. - Pierre 140

# IfcWallStandardCase: Mur de base:Struct. - Pierre 160 (9)
Type - PredefinedType: STANDARD; Material: Appareillage - Pierre taillé 0.16 m
Type - Pset_WallCommon - IsExternal: yes
Pset_QuantityTakeOff - Reference: Struct. - Pierre 160; sets with these values: 2
Pset_WallCommon - LoadBearing: yes; ExtendToStructure: no; Reference: Struct. - Pierre 160
Name | In
MurExt-010 | REZ-DE-CHAUSSÉE
2 x MurExt-011 | REZ-DE-CHAUSSÉE
2 x MurExt-012 | REZ-DE-CHAUSSÉE
2 x MurExt-004 | ÉTAGE
2 x MurExt-018 | TOITURE

# IfcWallStandardCase: Mur de base:Struct. - Pierre 170 (3)
In: ÉTAGE
Type - PredefinedType: STANDARD; Material: Appareillage - Pierre taillé 0.17 m
Type - Pset_WallCommon - IsExternal: yes
Pset_QuantityTakeOff - Reference: Struct. - Pierre 170; sets with these values: 2
Pset_WallCommon - LoadBearing: yes; ExtendToStructure: no; Reference: Struct. - Pierre 170
Name
MurExt-003
2 x MurExt-002

# IfcWallStandardCase: Mur de base:Struct. - Pierre 200 (3)
In: ÉTAGE
Type - PredefinedType: STANDARD; Material: Appareillage - Pierre taillé 0.2 m
Type - Pset_WallCommon - IsExternal: yes
Pset_QuantityTakeOff - Reference: Struct. - Pierre 200; sets with these values: 2
Pset_WallCommon - LoadBearing: yes; ExtendToStructure: no; Reference: Struct. - Pierre 200
Name
MurExt-016
MurExt-017
MurExt-018

# IfcWallStandardCase: Mur de base:Struct. - Pierre 220 (5)
In: REZ-DE-CHAUSSÉE
Type - PredefinedType: STANDARD; Material: Appareillage - Pierre taillé 0.22 m
Type - Pset_WallCommon - IsExternal: yes
Pset_QuantityTakeOff - Reference: Struct. - Pierre 220; sets with these values: 2
Pset_WallCommon - LoadBearing: yes; ExtendToStructure: no; Reference: Struct. - Pierre 220
Name
MurExt-010
MurExt-011
MurExt-012
2 x MurExt-002

# IfcWallStandardCase: Mur de base:Struct. - Pierre 230, MurExt-012
In: REZ-DE-CHAUSSÉE
Type - PredefinedType: STANDARD; Material: Appareillage - Pierre taillé 0.23 m
Type - Pset_WallCommon - IsExternal: yes
Pset_QuantityTakeOff - Reference: Struct. - Pierre 230; sets with these values: 2
Pset_WallCommon - LoadBearing: yes; ExtendToStructure: no; Reference: Struct. - Pierre 230

# IfcWallStandardCase: Mur de base:Struct. - Pierre 240, MurExt-003
In: REZ-DE-CHAUSSÉE
Type - PredefinedType: STANDARD; Material: Appareillage - Pierre taillé 0.24 m
Type - Pset_WallCommon - IsExternal: yes
Pset_QuantityTakeOff - Reference: Struct. - Pierre 240; sets with these values: 2
Pset_WallCommon - LoadBearing: yes; ExtendToStructure: no; Reference: Struct. - Pierre 240

# IfcWallStandardCase: Mur de base:Struct. - Pierre 260, MurExt-002
In: ÉTAGE
Type - PredefinedType: STANDARD; Material: Appareillage - Pierre taillé 0.26 m
Type - Pset_WallCommon - IsExternal: yes
Pset_QuantityTakeOff - Reference: Struct. - Pierre 260; sets with these values: 2
Pset_WallCommon - LoadBearing: yes; ExtendToStructure: no; Reference: Struct. - Pierre 260

# IfcWallStandardCase: Mur de base:Struct. - Pierre 280, MurExt-006
In: REZ-DE-CHAUSSÉE
Type - PredefinedType: STANDARD; Material: Appareillage - Pierre taillé 0.28 m
Type - Pset_WallCommon - IsExternal: yes
Pset_QuantityTakeOff - Reference: Struct. - Pierre 280; sets with these values: 2
Pset_WallCommon - LoadBearing: yes; ExtendToStructure: no; Reference: Struct. - Pierre 280

# IfcWallStandardCase: Mur de base:Struct. - Pierre 290 (5)
Type - PredefinedType: STANDARD; Material: Appareillage - Pierre taillé 0.29 m
Type - Pset_WallCommon - IsExternal: yes
Pset_QuantityTakeOff - Reference: Struct. - Pierre 290; sets with these values: 2
Pset_WallCommon - LoadBearing: yes; ExtendToStructure: no; Reference: Struct. - Pierre 290
Name | In
3 x MurExt-003 | REZ-DE-CHAUSSÉE
MurExt-007 | REZ-DE-CHAUSSÉE
MurExt-002 | ÉTAGE

# IfcWallStandardCase: Mur de base:Struct. - Pierre 300 (55)
Type - PredefinedType: STANDARD; Material: Appareillage - Pierre taillé 0.3 m
Type - Pset_WallCommon - IsExternal: yes
Pset_QuantityTakeOff - Reference: Struct. - Pierre 300; sets with these values: 2
Pset_WallCommon - LoadBearing: yes; ExtendToStructure: no; Reference: Struct. - Pierre 300
Name | In
MurExt-006 | REZ-DE-CHAUSSÉE
MurExt-007 | REZ-DE-CHAUSSÉE
MurExt-014 | VS
2 x MurExt-010 | VS
MurExt-017 | VS
2 x MurExt-013 | VS
3 x MurExt-012 | VS
MurExt-011 | VS
3 x MurExt-002 | VS
3 x MurExt-008 | VS
MurExt-007 | VS
MurExt-005 | VS
MurExt-004 | VS
MurExt-018 | VS
MurExt-016 | VS
MurExt-003 | VS
MurExt-009 | VS
2 x MurExt-003 | REZ-DE-CHAUSSÉE
MurExt-004 | REZ-DE-CHAUSSÉE
MurExt-005 | REZ-DE-CHAUSSÉE
2 x MurExt-009 | REZ-DE-CHAUSSÉE
MurExt-001 | REZ-DE-CHAUSSÉE
2 x MurExt-002 | REZ-DE-CHAUSSÉE
3 x MurExt-002 | ÉTAGE
MurExt-004 | ÉTAGE
MurExt-005 | ÉTAGE
MurExt-006 | ÉTAGE
MurExt-008 | ÉTAGE
2 x MurExt-009 | ÉTAGE
MurExt-010 | ÉTAGE
MurExt-011 | ÉTAGE
MurExt-014 | ÉTAGE
MurExt-016 | ÉTAGE
4 x MurExt-015 | ÉTAGE
MurExt-019 | TOITURE
MurExt-017 | TOITURE
MurExt-021 | TOITURE
MurExt-016 | TOITURE

# IfcWallStandardCase: Mur de base:Struct. - Pierre 310 (5)
Type - PredefinedType: STANDARD; Material: Appareillage - Pierre taillé 0.31 m
Type - Pset_WallCommon - IsExternal: yes
Pset_QuantityTakeOff - Reference: Struct. - Pierre 310; sets with these values: 2
Pset_WallCommon - LoadBearing: yes; ExtendToStructure: no; Reference: Struct. - Pierre 310
Name | In
2 x MurExt-003 | REZ-DE-CHAUSSÉE
MurExt-001 | REZ-DE-CHAUSSÉE
MurExt-006 | REZ-DE-CHAUSSÉE
MurExt-002 | ÉTAGE

# IfcWallStandardCase: Mur de base:Struct. - Pierre 330 (2)
Type - PredefinedType: STANDARD; Material: Appareillage - Pierre taillé 0.33 m
Type - Pset_WallCommon - IsExternal: yes
Pset_QuantityTakeOff - Reference: Struct. - Pierre 330; sets with these values: 2
Pset_WallCommon - LoadBearing: yes; Reference: Struct. - Pierre 330; ExtendToStructure: no
Name | In
MurExt-003 | REZ-DE-CHAUSSÉE
MurExt-003 | ÉTAGE

# IfcWallStandardCase: Mur de base:Struct. - Pierre 340 (2)
Type - PredefinedType: STANDARD; Material: Appareillage - Pierre taillé 0.34 m
Type - Pset_WallCommon - IsExternal: yes
Pset_QuantityTakeOff - Reference: Struct. - Pierre 340; sets with these values: 2
Pset_WallCommon - LoadBearing: yes; ExtendToStructure: no; Reference: Struct. - Pierre 340
Name | In
MurExt-003 | REZ-DE-CHAUSSÉE
MurExt-003 | ÉTAGE

# IfcWallStandardCase: Mur de base:Struct. - Pierre 360, MurExt-001
In: REZ-DE-CHAUSSÉE
Type - PredefinedType: STANDARD; Material: Appareillage - Pierre taillé 0.36 m
Type - Pset_WallCommon - IsExternal: yes
Pset_QuantityTakeOff - Reference: Struct. - Pierre 360; sets with these values: 2
Pset_WallCommon - LoadBearing: yes; ExtendToStructure: no; Reference: Struct. - Pierre 360

# IfcWallStandardCase: Mur de base:Struct. - Pierre 410 (2)
Type - PredefinedType: STANDARD; Material: Appareillage - Pierre taillé 0.41 m
Type - Pset_WallCommon - IsExternal: yes
Pset_QuantityTakeOff - Reference: Struct. - Pierre 410; sets with these values: 2
Pset_WallCommon - LoadBearing: yes; ExtendToStructure: no; Reference: Struct. - Pierre 410
Name | In
MurExt-015 | VS
MurExt-002 | REZ-DE-CHAUSSÉE

# IfcWallStandardCase: Mur de base:Struct. - Pierre 420 (2)
In: REZ-DE-CHAUSSÉE
Type - PredefinedType: STANDARD; Material: Appareillage - Pierre taillé 0.42 m
Type - Pset_WallCommon - IsExternal: yes
Pset_QuantityTakeOff - Reference: Struct. - Pierre 420; sets with these values: 2
Pset_WallCommon - LoadBearing: yes; ExtendToStructure: no; Reference: Struct. - Pierre 420
Name
MurExt-003
MurExt-004

# IfcWallStandardCase: Mur de base:Struct. - Pierre 430, MurExt-002
In: REZ-DE-CHAUSSÉE
Type - PredefinedType: STANDARD; Material: Appareillage - Pierre taillé 0.43 m
Type - Pset_WallCommon - IsExternal: yes
Pset_QuantityTakeOff - Reference: Struct. - Pierre 430; sets with these values: 2
Pset_WallCommon - LoadBearing: yes; ExtendToStructure: no; Reference: Struct. - Pierre 430

# IfcWallStandardCase: Mur de base:Struct. - Pierre 50, MurExt-004
In: REZ-DE-CHAUSSÉE
Type - PredefinedType: STANDARD; Material: Appareillage - Pierre taillé 0.05 m
Type - Pset_WallCommon - IsExternal: yes
Pset_QuantityTakeOff - Reference: Struct. - Pierre 50; sets with these values: 2
Pset_WallCommon - LoadBearing: yes; ExtendToStructure: no; Reference: Struct. - Pierre 50

# IfcWallStandardCase: Mur de base:Struct. - Pierre 70 (5)
In: REZ-DE-CHAUSSÉE
Type - PredefinedType: STANDARD; Material: Appareillage - Pierre taillé 0.07 m
Type - Pset_WallCommon - IsExternal: yes
Pset_QuantityTakeOff - Reference: Struct. - Pierre 70; sets with these values: 2
Pset_WallCommon - LoadBearing: yes; ExtendToStructure: no; Reference: Struct. - Pierre 70
Name
MurExt-015
MurExt-016
MurExt-014
MurExt-013
MurExt-017

# IfcWallStandardCase: Mur de base:Struct. - Pierre 80 (3)
In: REZ-DE-CHAUSSÉE
Type - PredefinedType: STANDARD; Material: Appareillage - Pierre taillé 0.08 m
Type - Pset_WallCommon - IsExternal: yes
Pset_QuantityTakeOff - Reference: Struct. - Pierre 80; sets with these values: 2
Pset_WallCommon - LoadBearing: yes; ExtendToStructure: no; Reference: Struct. - Pierre 80
Name
MurExt-012
MurExt-018
MurExt-007

# IfcWallStandardCase: Mur de base:Struct. - Pierre 90 (2)
In: REZ-DE-CHAUSSÉE
Type - PredefinedType: STANDARD; Material: Appareillage - Pierre taillé 0.09 m
Type - Pset_WallCommon - IsExternal: yes
Pset_QuantityTakeOff - Reference: Struct. - Pierre 90; sets with these values: 2
Pset_WallCommon - LoadBearing: yes; ExtendToStructure: no; Reference: Struct. - Pierre 90
Name
MurExt-013
MurExt-019

# IfcWallStandardCase: Mur de base:Struct. - Pierre 99 (4)
In: REZ-DE-CHAUSSÉE
Type - PredefinedType: STANDARD; Material: Appareillage - Pierre taillé 0.0992126 m
Type - Pset_WallCommon - IsExternal: yes
Pset_QuantityTakeOff - Reference: Struct. - Pierre 99; sets with these values: 2
Pset_WallCommon - LoadBearing: yes; ExtendToStructure: no; Reference: Struct. - Pierre 99
Name
2 x MurExt-004
2 x MurExt-003

# IfcWindow: Fen-002 (4)
In: ÉTAGE
Type - ParameterTakesPrecedence: no; Sizeable: no; Material: Peinture - Anthracite, Transp. - Verre clair (rapide)
Type - Pset_WindowCommon - IsExternal: no
OverallHeight: 1.52 m
Pset_WindowCommon - IsExternal: yes
Name | OverallWidth (m) | Pset_QuantityTakeOff, Reference = Pset_WindowCommon, Reference
Fen-002 291228:Fen-002 291228:198367 | 0.835 | Fen-002 291228
Fen-002 291508:Fen-002 291508:198368 | 0.81 | Fen-002 291508
Fen-002 291784:Fen-002 291784:198369 | 0.81 | Fen-002 291784
Fen-002 292060:Fen-002 292060:198370 | 0.685 | Fen-002 292060

# IfcWindow: Fen-002, Fen-002 23216:Fen-002 23216:195926
In: REZ-DE-CHAUSSÉE
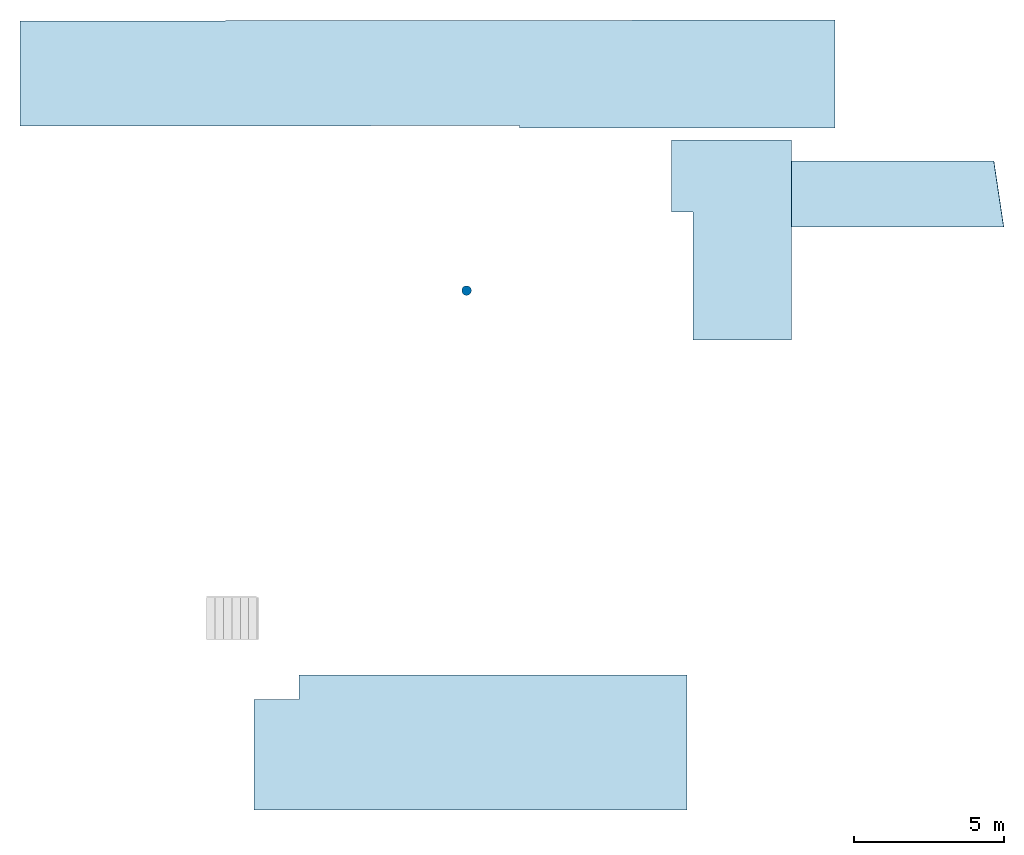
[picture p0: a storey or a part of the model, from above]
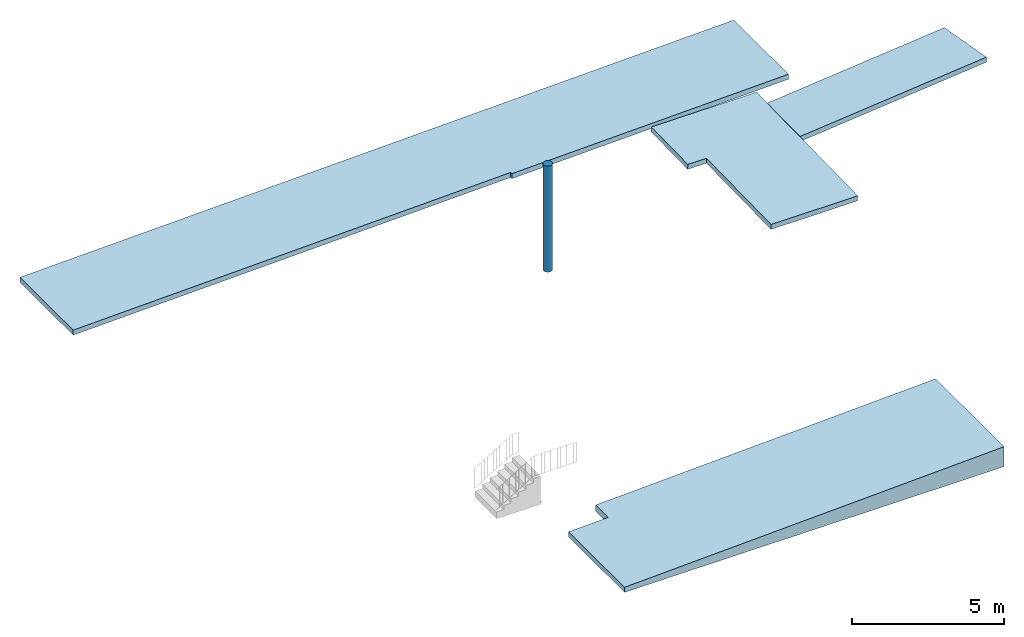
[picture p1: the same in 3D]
Properties of the parts of a building model (IFC2X3), part 3 of 3

# IfcWindow: Fen-002, Fen-002 23216:Fen-002 23216:195926
Type - ParameterTakesPrecedence: no; Sizeable: no; Material: Transp. - Verre clair (rapide), Peinture - Anthracite
Type - Pset_WindowCommon - IsExternal: no
OverallHeight: 2.2 m; OverallWidth: 3.14 m
Pset_QuantityTakeOff - Reference: Fen-002 23216
Pset_WindowCommon - IsExternal: yes; Reference: Fen-002 23216

# IfcWindow: Fen-003, Fen-003 30667 30667:Fen-003 30667 30667:196123
In: REZ-DE-CHAUSSÉE
Type - OperationType: SINGLE_PANEL; ParameterTakesPrecedence: no; Sizeable: no; Material: Peinture - Anthracite
Type - Pset_WindowCommon - IsExternal: no
OverallHeight: 2.23 m; OverallWidth: 1.58 m
Pset_QuantityTakeOff - Reference: Fen-003 30667 30667
Pset_WindowCommon - Reference: Fen-003 30667 30667

# IfcWindow: Fen-003, Fen-003 838242 838242:Fen-003 838242 838242:199068
In: TOITURE
Type - OperationType: SINGLE_PANEL; ParameterTakesPrecedence: no; Sizeable: no; Material: Transp. - Plexiglass
Type - Pset_WindowCommon - IsExternal: no
OverallHeight: 0.82 m; OverallWidth: 10.42 m
Pset_QuantityTakeOff - Reference: Fen-003 838242 838242
Pset_WindowCommon - Reference: Fen-003 838242 838242

# IfcWindow: Fen-003 (12)
Type - ParameterTakesPrecedence: no; Sizeable: no; Material: Peinture - Anthracite
Type - Pset_WindowCommon - IsExternal: no
Name | In | OverallHeight (m) | OverallWidth (m) | Pset_QuantityTakeOff, Reference = Pset_WindowCommon, Reference | IsExternal
Fen-003 16200:Fen-003 16200:195860 | REZ-DE-CHAUSSÉE | 0.55 | 1.56 | Fen-003 16200 | yes
Fen-003 50040:Fen-003 50040:196375 | REZ-DE-CHAUSSÉE | 1.36 | 3.04 | Fen-003 50040 | yes
Fen-003 50724:Fen-003 50724:196376 | REZ-DE-CHAUSSÉE | 2.44 | 1.04 | Fen-003 50724 | yes
Fen-003 51448:Fen-003 51448:196377 | REZ-DE-CHAUSSÉE | 1.36 | 2.04 | Fen-003 51448 | yes
Fen-003 139978:Fen-003 139978:196509 | REZ-DE-CHAUSSÉE | 0.48 | 2.9 | Fen-003 139978 | yes
Fen-003 140448:Fen-003 140448:196510 | REZ-DE-CHAUSSÉE | 2.12 | 1.08 | Fen-003 140448 | yes
Fen-003 141731:Fen-003 141731:196513 | REZ-DE-CHAUSSÉE | 1.36 | 3.04 | Fen-003 141731 | yes
Fen-003 142415:Fen-003 142415:196514 | REZ-DE-CHAUSSÉE | 2.44 | 1.04 | Fen-003 142415 | yes
Fen-003 143139:Fen-003 143139:196515 | REZ-DE-CHAUSSÉE | 1.36 | 2.04 | Fen-003 143139 | yes
Fen-003 240871:Fen-003 240871:197908 | ÉTAGE | 2.4 | 1.03 | Fen-003 240871 | yes
Fen-003 50040:Fen-003 50040:198435 | ÉTAGE | 1.36 | 3.04 | Fen-003 50040
Fen-003 50040:Fen-003 50040:198436 | ÉTAGE | 1.36 | 3.04 | Fen-003 50040

# IfcWindow: Fen-003 (7)
Type - ParameterTakesPrecedence: no; Sizeable: no; Material: Transp. - Verre clair (rapide)
Type - Pset_WindowCommon - IsExternal: no
Name | In | OverallHeight (m) | OverallWidth (m) | Pset_QuantityTakeOff, Reference = Pset_WindowCommon, Reference | IsExternal
Fen-003 52853:Fen-003 52853:196379 | REZ-DE-CHAUSSÉE | 2.45 | 1.495 | Fen-003 52853 | yes
Fen-003 259573:Fen-003 259573:198223 | ÉTAGE | 2.5 | 1.03 | Fen-003 259573 | yes
Fen-003 259573:Fen-003 259573:198227 | ÉTAGE | 2.5 | 1.03 | Fen-003 259573
Fen-003 260509:Fen-003 260509:198230 | ÉTAGE | 2.5 | 1.03 | Fen-003 260509 | yes
Fen-003 277032:Fen-003 277032:198273 | ÉTAGE | 2.5 | 1.53 | Fen-003 277032 | yes
Fen-003 278542:Fen-003 278542:198278 | ÉTAGE | 2.5 | 1.53 | Fen-003 278542 | yes
Fen-003 803126:Fen-003 803126:198812 | ÉTAGE | 2.5 | 1.13 | Fen-003 803126 | yes

# IfcWindow: Fen-003, Fen-003 14240:Fen-003 14240:195847
In: REZ-DE-CHAUSSÉE
Type - ParameterTakesPrecedence: no; Sizeable: no; Material: Transp. - Verre clair (rapide), Enduit - Beige nature
Type - Pset_WindowCommon - IsExternal: no; ThermalTransmittance: 0 kg/K/s3; GlazingAreaFraction: 0.7392
OverallHeight: 0.5 m; OverallWidth: 1.6 m
Pset_QuantityTakeOff - Reference: Fen-003 14240
Pset_WindowCommon - IsExternal: yes; Reference: Fen-003 14240

# IfcWindow: Fen-003 (12)
In: ÉTAGE
Type - ParameterTakesPrecedence: no; Sizeable: no; Material: Transp. - Verre clair (rapide), Peinture - Anthracite
Type - Pset_WindowCommon - IsExternal: no
OverallHeight: 2.5 m
Name | OverallWidth (m) | Pset_QuantityTakeOff, Reference = Pset_WindowCommon, Reference | IsExternal
Fen-003 258897:Fen-003 258897:198220 | 0.99 | Fen-003 258897 | yes
Fen-003 258897:Fen-003 258897:198221 | 0.99 | Fen-003 258897
Fen-003 258897:Fen-003 258897:198224 | 0.99 | Fen-003 258897
Fen-003 258897:Fen-003 258897:198225 | 0.99 | Fen-003 258897
Fen-003 259891:Fen-003 259891:198228 | 0.919951 | Fen-003 259891 | yes
Fen-003 260073:Fen-003 260073:198229 | 0.92 | Fen-003 260073 | yes
Fen-003 277214:Fen-003 277214:198274 | 1.01 | Fen-003 277214 | yes
Fen-003 277554:Fen-003 277554:198276 | 1.53 | Fen-003 277554 | yes
Fen-003 279195:Fen-003 279195:198306 | 1.5 | Fen-003 279195 | yes
Fen-003 287570:Fen-003 287570:198354 | 1 | Fen-003 287570 | yes
Fen-003 287570:Fen-003 287570:198355 | 1 | Fen-003 287570
Fen-003 803318:Fen-003 803318:198813 | 0.9 | Fen-003 803318 | yes

# IfcWindow: Fen-004 (3)
Type - ParameterTakesPrecedence: no; Sizeable: no; Material: Peinture - Anthracite
Type - Pset_WindowCommon - IsExternal: no
Pset_WindowCommon - IsExternal: yes
Name | In | OverallHeight (m) | OverallWidth (m) | Pset_QuantityTakeOff, Reference = Pset_WindowCommon, Reference
Fen-004 27626:Fen-004 27626:195942 | REZ-DE-CHAUSSÉE | 2.5 | 1.03 | Fen-004 27626
Fen-004 244126:Fen-004 244126:197915 | ÉTAGE | 2.76 | 1.6 | Fen-004 244126
Fen-004 260945:Fen-004 260945:198231 | ÉTAGE | 2.5 | 1.13 | Fen-004 260945

# IfcWindow: Fen-004 (6)
Type - ParameterTakesPrecedence: no; Sizeable: no; Material: Transp. - Verre clair (rapide)
Type - Pset_WindowCommon - IsExternal: no
Name | In | OverallHeight (m) | OverallWidth (m) | Pset_QuantityTakeOff, Reference = Pset_WindowCommon, Reference | IsExternal
Fen-004 28724:Fen-004 28724:195945 | REZ-DE-CHAUSSÉE | 2.5 | 1.52 | Fen-004 28724 | yes
Fen-004 55397:Fen-004 55397:196390 | REZ-DE-CHAUSSÉE | 2.6 | 1.32 | Fen-004 55397 | yes
Fen-004 55975:Fen-004 55975:196392 | REZ-DE-CHAUSSÉE | 2.6 | 1.32 | Fen-004 55975 | yes
Fen-004 55397:Fen-004 55397:196418 | REZ-DE-CHAUSSÉE | 2.6 | 1.32 | Fen-004 55397
Fen-004 55975:Fen-004 55975:196420 | REZ-DE-CHAUSSÉE | 2.6 | 1.32 | Fen-004 55975
Fen-004 280209:Fen-004 280209:198309 | ÉTAGE | 2.05 | 3 | Fen-004 280209 | yes

# IfcWindow: Fen-004 (11)
Type - ParameterTakesPrecedence: no; Sizeable: no; Material: Transp. - Verre clair (rapide), Peinture - Anthracite
Type - Pset_WindowCommon - IsExternal: no
Name | In | OverallHeight (m) | OverallWidth (m) | Pset_QuantityTakeOff, Reference = Pset_WindowCommon, Reference | IsExternal
Fen-004 53039:Fen-004 53039:196380 | REZ-DE-CHAUSSÉE | 2.45 | 0.835 | Fen-004 53039 | yes
Fen-004 53221:Fen-004 53221:196381 | REZ-DE-CHAUSSÉE | 1.18 | 0.685 | Fen-004 53221 | yes
Fen-004 53403:Fen-004 53403:196382 | REZ-DE-CHAUSSÉE | 1.18 | 0.81 | Fen-004 53403 | yes
Fen-004 53585:Fen-004 53585:196383 | REZ-DE-CHAUSSÉE | 2.28 | 0.81 | Fen-004 53585 | yes
Fen-004 54853:Fen-004 54853:196389 | REZ-DE-CHAUSSÉE | 2.6 | 1.32 | Fen-004 54853 | yes
Fen-004 54853:Fen-004 54853:196391 | REZ-DE-CHAUSSÉE | 2.6 | 1.32 | Fen-004 54853
Fen-004 56171:Fen-004 56171:196393 | REZ-DE-CHAUSSÉE | 2.6 | 1.32 | Fen-004 56171 | yes
Fen-004 54853:Fen-004 54853:196417 | REZ-DE-CHAUSSÉE | 2.6 | 1.32 | Fen-004 54853
Fen-004 54853:Fen-004 54853:196419 | REZ-DE-CHAUSSÉE | 2.6 | 1.32 | Fen-004 54853
Fen-004 56171:Fen-004 56171:196421 | REZ-DE-CHAUSSÉE | 2.6 | 1.32 | Fen-004 56171
Fen-004 278724:Fen-004 278724:198279 | ÉTAGE | 2.5 | 0.8 | Fen-004 278724 | yes

# IfcWindow: Fen-005 (2)
In: ÉTAGE
Type - ParameterTakesPrecedence: no; Sizeable: no; Material: Transp. - Verre clair (rapide), Peinture - Anthracite
Type - Pset_WindowCommon - IsExternal: no
OverallHeight: 2.5 m; OverallWidth: 0.99 m
Pset_QuantityTakeOff - Reference: Fen-005 259127
Pset_WindowCommon - Reference: Fen-005 259127
Name (Fen-005 259127:Fen-005 259127:...)
198222 | Pset_WindowCommon - IsExternal: yes
198226

# IfcWindow: Fen-007, Fen-007 243032:Fen-007 243032:197912
In: ÉTAGE
Type - ParameterTakesPrecedence: no; Sizeable: no; Material: Peinture - Anthracite
Type - Pset_WindowCommon - IsExternal: no
OverallHeight: 2.48 m; OverallWidth: 3.3 m
Pset_QuantityTakeOff - Reference: Fen-007 243032
Pset_WindowCommon - IsExternal: yes; Reference: Fen-007 243032

# IfcWindow: Fen-007 (2)
Type - ParameterTakesPrecedence: no; Sizeable: no; Material: Transp. - Verre clair (rapide)
Type - Pset_WindowCommon - IsExternal: no
Pset_WindowCommon - IsExternal: yes
Name | In | OverallHeight (m) | OverallWidth (m) | Pset_QuantityTakeOff, Reference = Pset_WindowCommon, Reference
Fen-007 9126:Fen-007 9126:195811 | REZ-DE-CHAUSSÉE | 2.2 | 1.1 | Fen-007 9126
Fen-007 242167:Fen-007 242167:197910 | ÉTAGE | 2.76 | 3.3 | Fen-007 242167

# IfcWindow: Fen-007 (7)
In: REZ-DE-CHAUSSÉE
Type - ParameterTakesPrecedence: no; Sizeable: no; Material: Transp. - Verre clair (rapide), Bois - Chêne clair
Type - Pset_WindowCommon - IsExternal: no
OverallHeight: 2.25 m; OverallWidth: 0.47 m
Pset_QuantityTakeOff - Reference: Fen-007 191509
Pset_WindowCommon - Reference: Fen-007 191509
Name (Fen-007 191509:Fen-007 191509:...)
196850 | Pset_WindowCommon - IsExternal: yes
196851
196852
196854
196855
196856
196858

# IfcWindow: Fen-007 (7)
In: REZ-DE-CHAUSSÉE
Type - ParameterTakesPrecedence: no; Sizeable: no; Material: Transp. - Verre clair (rapide), Peinture - Anthracite
Type - Pset_WindowCommon - IsExternal: no
Name | OverallHeight (m) | OverallWidth (m) | Pset_QuantityTakeOff, Reference = Pset_WindowCommon, Reference | IsExternal
Fen-007 9315:Fen-007 9315:195812 | 2.2 | 1.1 | Fen-007 9315 | yes
Fen-007 9501:Fen-007 9501:195813 | 2.2 | 1.1 | Fen-007 9501 | yes
Fen-007 26298:Fen-007 26298:195936 | 1.5 | 0.94 | Fen-007 26298 | yes
Fen-007 26480:Fen-007 26480:195937 | 1.5 | 0.94 | Fen-007 26480 | yes
Fen-007 27156:Fen-007 27156:195940 | 2.5 | 0.94 | Fen-007 27156 | yes
Fen-007 27156:Fen-007 27156:195941 | 2.5 | 0.94 | Fen-007 27156
Fen-007 27808:Fen-007 27808:195943 | 2.5 | 0.39 | Fen-007 27808 | yes

# IfcWindow: Luc-001, Luc-001 804245 804245:Luc-001 804245 804245:198883
In: TOITURE
Type - ParameterTakesPrecedence: no; Sizeable: no; Material: Métal - Acier inoxydable
Type - Pset_WindowCommon - IsExternal: no
OverallHeight: 0.184887 m; OverallWidth: 1.00463 m
Pset_QuantityTakeOff - Reference: Luc-001 804245 804245
Pset_WindowCommon - Reference: Luc-001 804245 804245
